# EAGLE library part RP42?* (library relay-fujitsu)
Power PCB Relay RP II/2 Schrack 2 pole 8 A Source: http://www.schrack.com/.. 5844.pdf

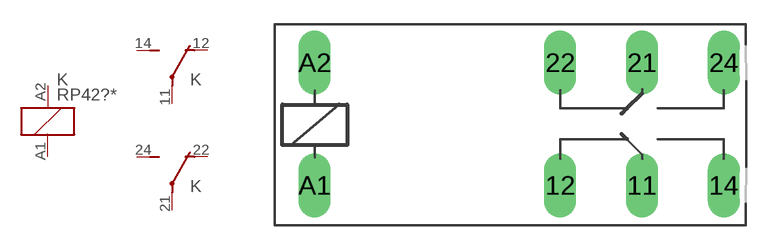
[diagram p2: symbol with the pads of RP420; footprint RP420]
Designator prefix K; gates 1=K 2=U 3=U

## RP420005, RP420006, RP420012, RP420024, RP420048, RP420060, RP420110  [RP420]
11  2:P  pas
12  2:O  pas
14  2:S  pas
21  3:P  pas
22  3:O  pas
24  3:S  pas
A1  1:2  pas
A2  1:1  pas

## RP421005, RP421006, RP421012, RP421024, RP421048, RP421060, RP421110  [RP420]
Pads as for RP420

## Footprint RP420 (pad centres in mm)
RELAY 2 x switch, Schrack
drill 1.321 long: 11 16.51,-3.81; 12 11.43,-3.81; 14 21.59,-3.81; 21 16.51,3.81; 22 11.43,3.81; 24 21.59,3.81; A1 -3.81,-3.81; A2 -3.81,3.81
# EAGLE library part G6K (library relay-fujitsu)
Low Signal Relay oeiwcsnts1.omron.com/.. D20G6K0100.pdf

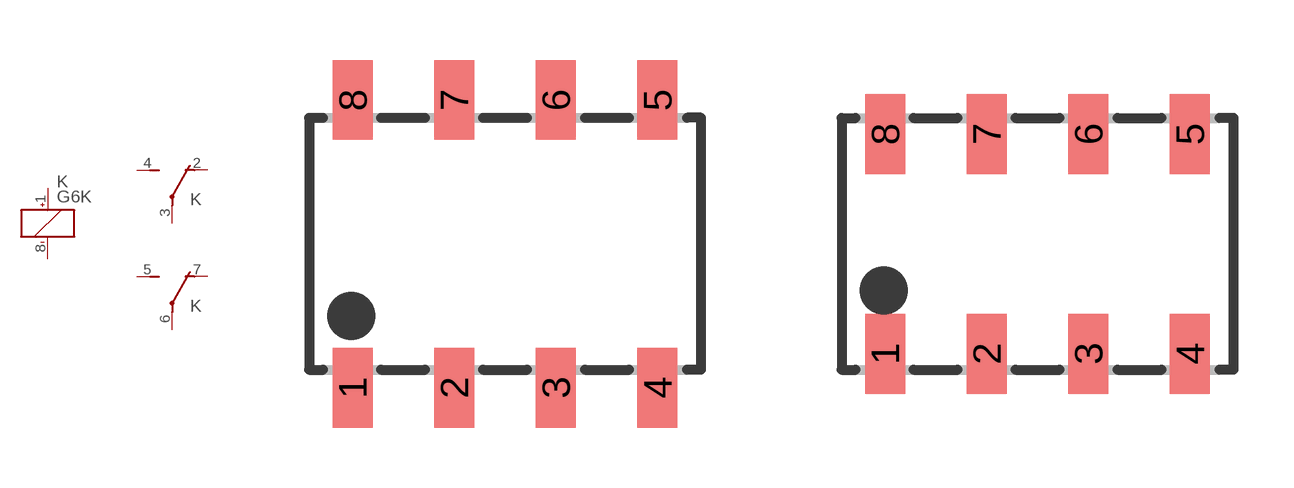
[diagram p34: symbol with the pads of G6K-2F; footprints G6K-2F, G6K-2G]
Designator prefix K; gates 1=K+- 2=U 3=U

## G6K-2F  [G6K-2F]
1  1:+  pas
2  2:O  pas
3  2:P  pas
4  2:S  pas
5  3:S  pas
6  3:P  pas
7  3:O  pas
8  1:-  pas

## G6K-2G  [G6K-2G]
Pads as for G6K-2F

## G6K-2P  [G6K-2P]
Pads as for G6K-2F

## G6K-2F-Y  [G6K-2F-Y]
Pads as for G6K-2F

## G6K-2G-Y  [G6K-2G-Y]
Pads as for G6K-2F

## G6K-2P-Y  [G6K-2P-Y]
Pads as for G6K-2F

## G6KU-2F-Y  [G6KU-2F-Y]
Pads as for G6K-2F

## G6KU-2G-Y  [G6KU-2G-Y]
Pads as for G6K-2F

## G6KU-2P-Y  [G6KU-2P-Y]
Pads as for G6K-2F

## Footprint G6K-2F (pad centres in mm)
Low Signal Relay oeiwcsnts1.omron.com/.. D20G6K0100.pdf
smd 1 x 2: 1 -3.81,-3.6; 2 -1.27,-3.6; 3 1.27,-3.6; 4 3.81,-3.6; 5 3.81,3.6; 6 1.27,3.6; 7 -1.27,3.6; 8 -3.81,3.6

## Footprint G6K-2G (pad centres in mm)
Low Signal Relay oeiwcsnts1.omron.com/.. D20G6K0100.pdf
smd 1 x 2: 1 -3.81,-2.75; 2 -1.27,-2.75; 3 1.27,-2.75; 4 3.81,-2.75; 5 3.81,2.75; 6 1.27,2.75; 7 -1.27,2.75; 8 -3.81,2.75

## Footprint G6K-2P (pad centres in mm)
Low Signal Relay oeiwcsnts1.omron.com/.. D20G6K0100.pdf
drill 0.8 octagon: 1 -2.54,-2.54; 2 0,-2.54; 3 2.54,-2.54; 4 5.08,-2.54; 5 5.08,2.54; 6 2.54,2.54; 7 0,2.54; 8 -2.54,2.54

## Footprint G6K-2F-Y (pad centres in mm)
Low Signal Relay oeiwcsnts1.omron.com/.. D20G6K0100.pdf
smd 1.2 x 1.8: 1 -3.8,-3.5; 2 -0.6,-3.5; 3 1.6,-3.5; 4 3.8,-3.5; 5 3.8,3.5; 6 1.6,3.5; 7 -0.6,3.5; 8 -3.8,3.5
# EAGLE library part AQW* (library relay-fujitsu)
PhotoMOS Relay NAiS Source: http://www.mew-europe.com/.. pti_en.pdf

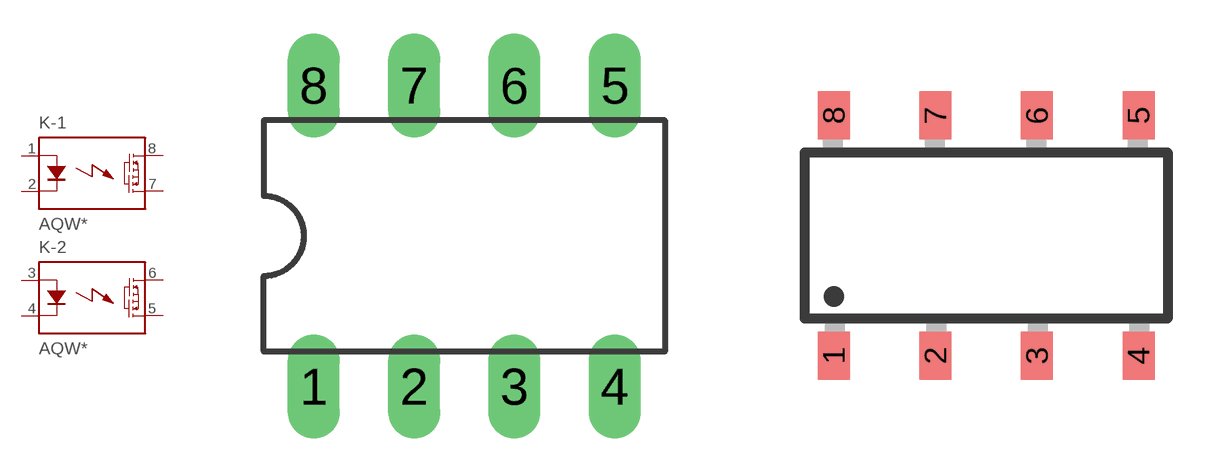
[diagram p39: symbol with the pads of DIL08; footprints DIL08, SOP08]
Designator prefix K; gates -1=PHOTO-RELAY-2S -2=PHOTO-RELAY-2S

## AQW21, AQW22, AQW25, AQW27, AQW41, AQW45, AQW654  [DIL08]
1  -1:A  pas
2  -1:K  pas
3  -2:A  pas
4  -2:K  pas
5  -2:D2  pas
6  -2:D1  pas
7  -1:D2  pas
8  -1:D1  pas

## AQW21SOP  [SOP08]
Pads as for DIL08

## AQW654SMD  [DIL08SMD]
Pads as for DIL08

## Footprint DIL08 (pad centres in mm)
Dual In Line Package
drill 0.813 long: 1 -3.81,-3.81; 2 -1.27,-3.81; 3 1.27,-3.81; 4 3.81,-3.81; 5 3.81,3.81; 6 1.27,3.81; 7 -1.27,3.81; 8 -3.81,3.81

## Footprint SOP08 (pad centres in mm)
SOP 08 - AQW21, AQW61 Series NAiS Source: http://www.mew-europe.com/.. pti_en.pdf
smd 0.8 x 1.2: 1 -3.81,-3; 2 -1.27,-3; 3 1.27,-3; 4 3.81,-3; 5 3.81,3; 6 1.27,3; 7 -1.27,3; 8 -3.81,3

## Footprint DIL08SMD (pad centres in mm)
DIL08 NAiS Source: http://www.mew-europe.com/.. pti_en.pdf
smd 1.5 x 1.9: 1 -3.81,-4.15; 2 -1.27,-4.15; 3 1.27,-4.15; 4 3.81,-4.15; 5 3.81,4.15; 6 1.27,4.15; 7 -1.27,4.15; 8 -3.81,4.15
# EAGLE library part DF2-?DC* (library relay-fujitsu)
HIGHLY SENSITIVE DIP MINIATURE RELAY NAiS Single side stable / 1 coil latching Source: http://www.mew-europe.com/.. en_ds_61002_0000.pdf

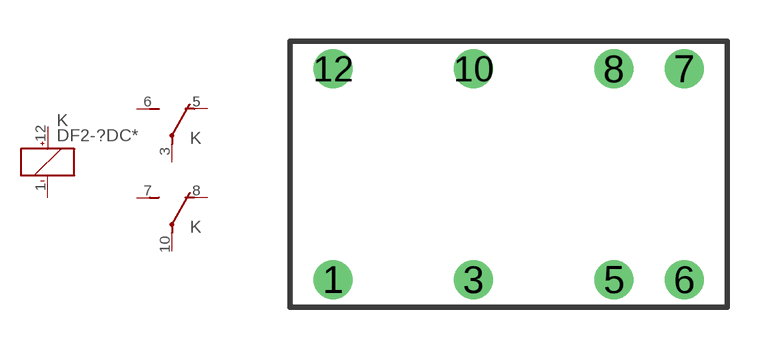
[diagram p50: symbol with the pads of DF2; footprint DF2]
Designator prefix K; gates 1=K+- 2=U 3=U

## DF2-DC1.5V, DF2-DC12V, DF2-DC24V, DF2-DC3V, DF2-DC5V, DF2-DC6V, DF2-DC9V  [DF2]
1  1:-  pas
3  2:P  pas
5  2:O  pas
6  2:S  pas
7  3:S  pas
8  3:O  pas
10  3:P  pas
12  1:+  pas

## DF2-L-DC1.5V, DF2-L-DC12V, DF2-L-DC24V, DF2-L-DC3V, DF2-L-DC5V, DF2-L-DC6V, DF2-L-DC9V  [DF2]
Pads as for DF2

## Footprint DF2 (pad centres in mm)
HIGHLY SENSITIVE DIP MINIATURE RELAY Source: http://www.mew-europe.com/.. en_ds_61002_0000.pdf
drill 0.9 round: 1 -6.35,-3.81; 3 -1.27,-3.81; 5 3.81,-3.81; 6 6.35,-3.81; 7 6.35,3.81; 8 3.81,3.81; 10 -1.27,3.81; 12 -6.35,3.81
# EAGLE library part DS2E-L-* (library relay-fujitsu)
DS-RELAYS HIGHLY SENSITIVE 1500 V FCC SURGE NAiS WITHSTANDING MINIATURE RELAY Source: http://www.mew-europe.com/.. en_ds_61005_0001.pdf

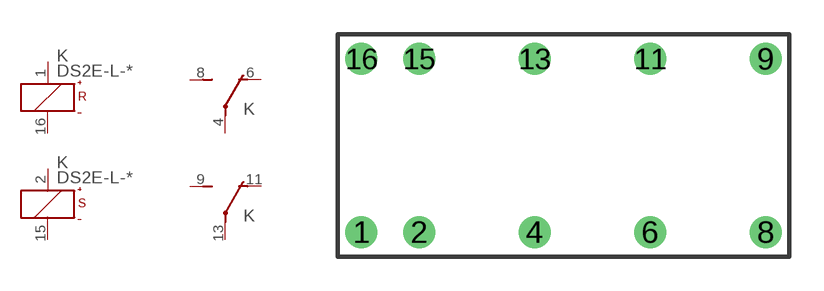
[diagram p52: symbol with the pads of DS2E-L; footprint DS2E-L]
Designator prefix K; gates 1=K+-R 2=K+-S 3=U 4=U

## DS2E-L-1.5V, DS2E-L-12V, DS2E-L-24V, DS2E-L-3V, DS2E-L-48V, DS2E-L-5V, DS2E-L-6V, DS2E-L-9V  [DS2E-L]
1  1:+  pas
2  2:+  pas
4  3:P  pas
6  3:O  pas
8  3:S  pas
9  4:S  pas
11  4:O  pas
13  4:P  pas
15  2:-  pas
16  1:-  pas

## Footprint DS2E-L (pad centres in mm)
DS-RELAYS HIGHLY SENSITIVE 1500 V FCC SURGE NAiS WITHSTANDING MINIATURE RELAY Source: http://www.mew-europe.com/.. en_ds_61005_0001.pdf
drill 0.9 round: 1 -8.89,-3.81; 2 -6.35,-3.81; 4 -1.27,-3.81; 6 3.81,-3.81; 8 8.89,-3.81; 9 8.89,3.81; 11 3.81,3.81; 13 -1.27,3.81; 15 -6.35,3.81; 16 -8.89,3.81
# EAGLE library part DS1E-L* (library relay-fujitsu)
DS-RELAYS HIGHLY SENSITIVE 1500 V FCC SURGE NAiS WITHSTANDING MINIATURE RELAY Source: http://www.mew-europe.com/.. en_ds_61005_0001.pdf

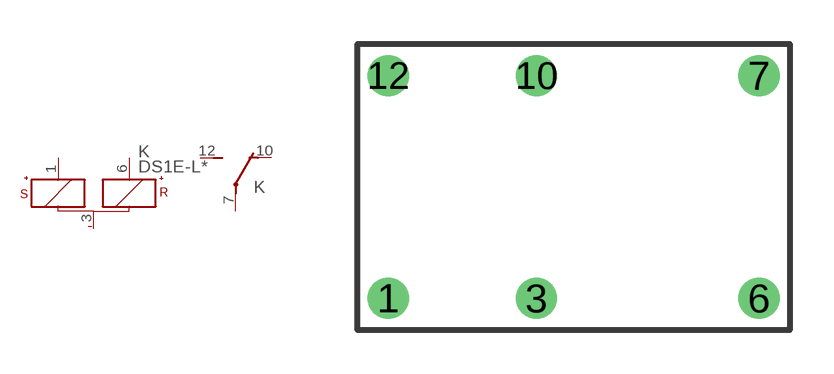
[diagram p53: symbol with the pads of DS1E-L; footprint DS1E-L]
Designator prefix K; gates 2=U 1=+KS+KR-

## DS1E-L1.5V, DS1E-L12V, DS1E-L24V, DS1E-L3V, DS1E-L48V, DS1E-L5V, DS1E-L6V, DS1E-L9V  [DS1E-L]
1  1:S+  pas
3  1:-  pas
6  1:R+  pas
7  2:P  pas
10  2:O  pas
12  2:S  pas

## Footprint DS1E-L (pad centres in mm)
DS-RELAYS HIGHLY SENSITIVE 1500 V FCC SURGE NAiS WITHSTANDING MINIATURE RELAY Source: http://www.mew-europe.com/.. en_ds_61005_0001.pdf
drill 0.9 round: 1 -6.35,-3.81; 3 -1.27,-3.81; 6 6.35,-3.81; 7 6.35,3.81; 10 -1.27,3.81; 12 -6.35,3.81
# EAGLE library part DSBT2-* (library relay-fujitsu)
DS-BT RELAYS 4,000 V BREAKDOWN VOLTAGE NAiS Source: http://www.mew-europe.com/.. en_ds_61005_0010.pdf

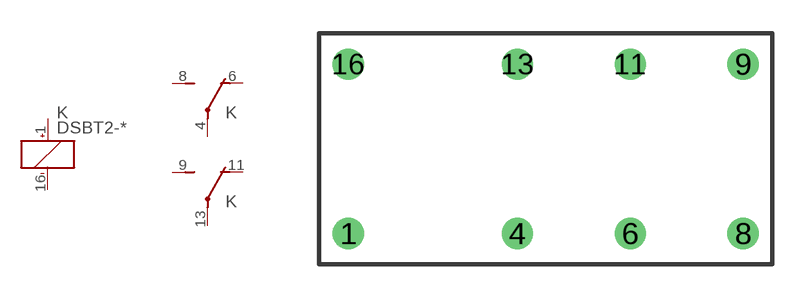
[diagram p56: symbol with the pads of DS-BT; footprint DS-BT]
Designator prefix K; gates 1=K+- 2=U 3=U

## DSBT2-M-2D-DC1.5V, DSBT2-M-2D-DC12V, DSBT2-M-2D-DC24V, DSBT2-M-2D-DC3V, DSBT2-M-2D-DC5V, DSBT2-M-2D-DC6V, DSBT2-M-2D-DC9V, DSBT2-S-DC1.5V, DSBT2-S-DC12V, DSBT2-S-DC24V, DSBT2-S-DC3V, DSBT2-S-DC5V, DSBT2-S-DC6V, DSBT2-S-DC9V  [DS-BT]
1  1:+  pas
4  2:P  pas
6  2:O  pas
8  2:S  pas
9  3:S  pas
11  3:O  pas
13  3:P  pas
16  1:-  pas

## Footprint DS-BT (pad centres in mm)
DS-BT RELAYS 4,000 V BREAKDOWN VOLTAGE NAiS Source: http://www.mew-europe.com/.. en_ds_61005_0010.pdf
drill 0.9 round: 1 -8.89,-3.81; 4 -1.27,-3.81; 6 3.81,-3.81; 8 8.89,-3.81; 9 8.89,3.81; 11 3.81,3.81; 13 -1.27,3.81; 16 -8.89,3.81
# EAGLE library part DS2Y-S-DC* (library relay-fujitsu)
MINIATURE RELAY NAiS Source: http://www.mew-europe.com/.. en_ds_61005_0023.pdf

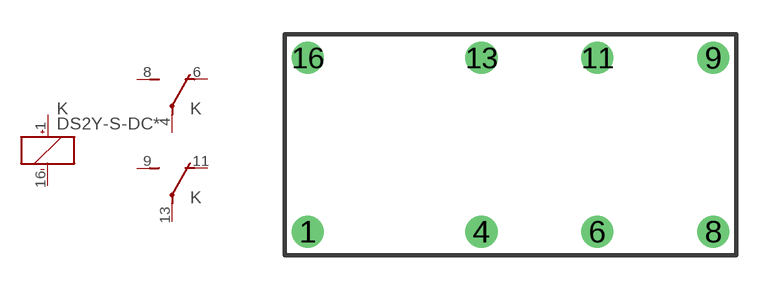
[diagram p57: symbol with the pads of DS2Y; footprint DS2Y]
Designator prefix K; gates 1=K+- 2=U 3=U

## DS2Y-S-DC1.5V, DS2Y-S-DC12V, DS2Y-S-DC24V, DS2Y-S-DC3V, DS2Y-S-DC48V, DS2Y-S-DC5V, DS2Y-S-DC6V, DS2Y-S-DC9V  [DS2Y]
1  1:+  pas
4  2:P  pas
6  2:O  pas
8  2:S  pas
9  3:S  pas
11  3:O  pas
13  3:P  pas
16  1:-  pas

## Footprint DS2Y (pad centres in mm)
MINIATURE RELAY NAiS Source: http://www.mew-europe.com/.. en_ds_61005_0023.pdf
drill 0.9 round: 1 -8.89,-3.81; 4 -1.27,-3.81; 6 3.81,-3.81; 8 8.89,-3.81; 9 8.89,3.81; 11 3.81,3.81; 13 -1.27,3.81; 16 -8.89,3.81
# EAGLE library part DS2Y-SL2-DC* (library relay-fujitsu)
MINIATURE RELAY NAiS Source: http://www.mew-europe.com/.. en_ds_61005_0023.pdf

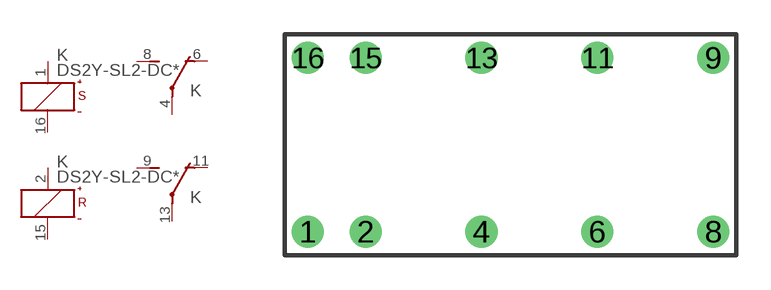
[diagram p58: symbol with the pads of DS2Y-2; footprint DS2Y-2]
Designator prefix K; gates 1=U 2=U S=K+-S R=K+-R

## DS2Y-SL2-DC1.5V, DS2Y-SL2-DC12V, DS2Y-SL2-DC24V, DS2Y-SL2-DC3V, DS2Y-SL2-DC48V, DS2Y-SL2-DC5V, DS2Y-SL2-DC6V, DS2Y-SL2-DC9V  [DS2Y-2]
1  S:+  pas
2  R:+  pas
4  1:P  pas
6  1:O  pas
8  1:S  pas
9  2:S  pas
11  2:O  pas
13  2:P  pas
15  R:-  pas
16  S:-  pas

## Footprint DS2Y-2 (pad centres in mm)
MINIATURE RELAY NAiS Source: http://www.mew-europe.com/.. en_ds_61005_0023.pdf
drill 0.9 round: 1 -8.89,-3.81; 2 -6.35,-3.81; 4 -1.27,-3.81; 6 3.81,-3.81; 8 8.89,-3.81; 9 8.89,3.81; 11 3.81,3.81; 13 -1.27,3.81; 15 -6.35,3.81; 16 -8.89,3.81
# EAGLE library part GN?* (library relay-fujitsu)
ULTRA-SMALL PACKAGE SLIM POLARIZED RELAY NAiS Source: http://www.mew-europe.com/.. en_ds_61007_0000.pdf

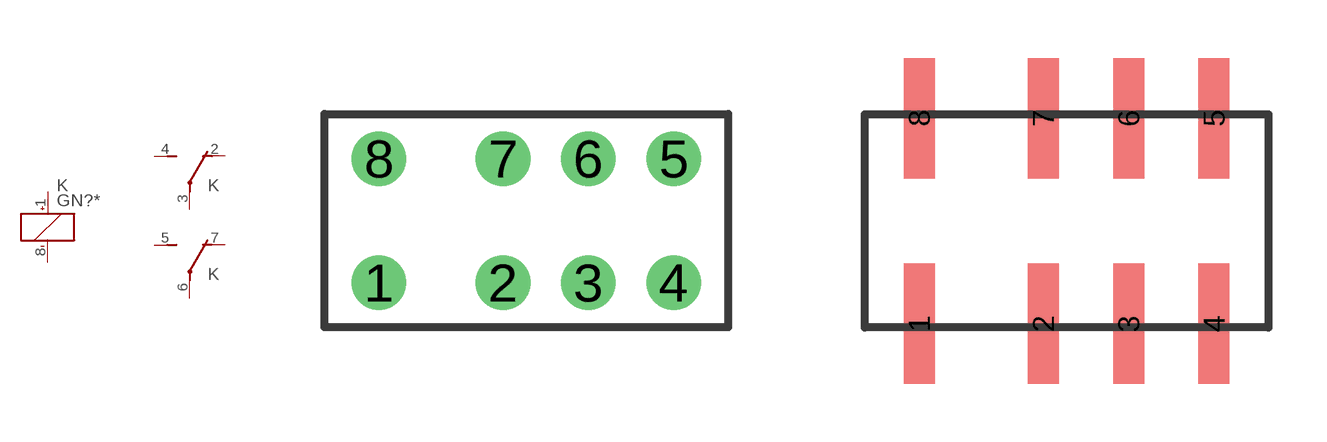
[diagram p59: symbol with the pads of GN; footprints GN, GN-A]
Designator prefix K; gates R=K+- S=U T=U

## GN20003, GN20006, GN20009, GN20012, GN2001H, GN20024, GN2004H  [GN]
1  R:+  pas
2  S:O  pas
3  S:P  pas
4  S:S  pas
5  T:S  pas
6  T:P  pas
7  T:O  pas
8  R:-  pas

## GN21003, GN21006, GN21009, GN21012, GN2101H, GN21024, GN2104H  [GN]
1  R:-  pas
2  S:O  pas
3  S:P  pas
4  S:S  pas
5  T:S  pas
6  T:P  pas
7  T:O  pas
8  R:+  pas

## GN200A03, GN200A06, GN200A09, GN200A12, GN200A1H, GN200A24, GN200A4H  [GN-A]
Pads as for GN

## GN200S03, GN200S06, GN200S09, GN200S12, GN200S1H, GN200S24, GN200S4H  [GN-S]
Pads as for GN

## GN210A03, GN210A06, GN210A09, GN210A12, GN210A1H, GN210A24, GN210A4H  [GN-A]
Pads as for GN

## GN210S03, GN210S06, GN210S09, GN210S12, GN210S1H, GN210S24, GN210S4H  [GN-S]
Pads as for GN

## Footprint GN (pad centres in mm)
ULTRA-SMALL PACKAGE SLIM POLARIZED RELAY NAiS Source: http://www.mew-europe.com/.. en_ds_61007_0000.pdf
drill 0.9 round: 1 -3.835,-1.6; 2 -0.635,-1.6; 3 1.565,-1.6; 4 3.765,-1.6; 5 3.765,1.6; 6 1.565,1.6; 7 -0.635,1.6; 8 -3.835,1.6

## Footprint GN-A (pad centres in mm)
ULTRA-SMALL PACKAGE SLIM POLARIZED RELAY NAiS Source: http://www.mew-europe.com/.. en_ds_61007_0000.pdf
smd 0.8 x 3.1: 1 -3.835,-2.65; 2 -0.635,-2.65; 3 1.565,-2.65; 4 3.765,-2.65; 5 3.765,2.65; 6 1.565,2.65; 7 -0.635,2.65; 8 -3.835,2.65

## Footprint GN-S (pad centres in mm)
ULTRA-SMALL PACKAGE SLIM POLARIZED RELAY NAiS Source: http://www.mew-europe.com/.. en_ds_61007_0000.pdf
smd 0.8 x 2.25: 1 -3.835,-2.225; 2 -0.635,-2.225; 3 1.565,-2.225; 4 3.765,-2.225; 5 3.765,2.225; 6 1.565,2.225; 7 -0.635,2.225; 8 -3.835,2.225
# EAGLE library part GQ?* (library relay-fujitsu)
ULTRA-SMALL PACKAGE FLAT POLARIZED RELAY NAiS Source: http://www.mew-europe.com/.. en_ds_61008_0000.pdf

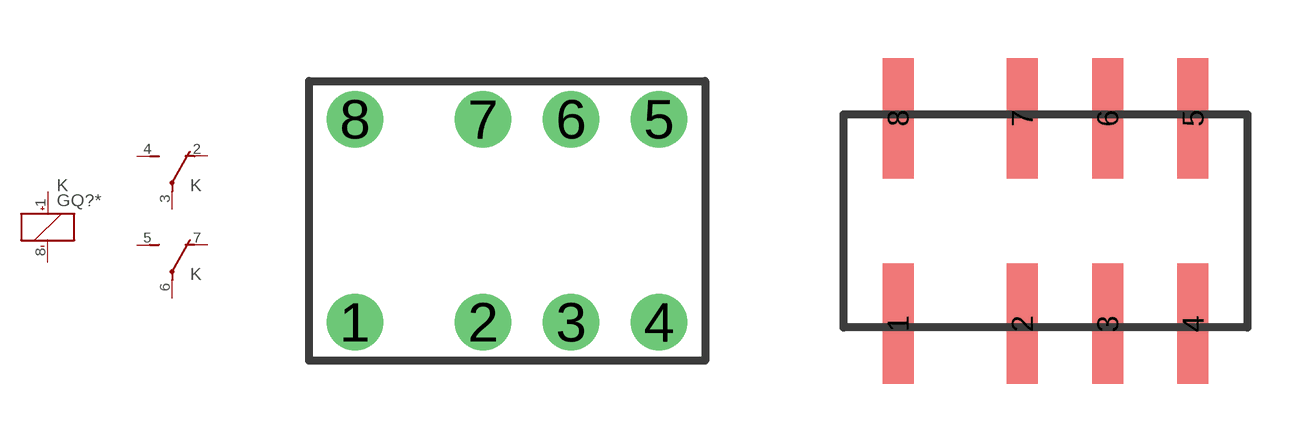
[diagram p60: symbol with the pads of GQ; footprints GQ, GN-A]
Designator prefix K; gates 1=K+- 2=U 3=U

## GQ20003, GQ20006, GQ20009, GQ20012, GQ2001H, GQ20024, GQ2004H  [GQ]
1  1:+  pas
2  2:O  pas
3  2:P  pas
4  2:S  pas
5  3:S  pas
6  3:P  pas
7  3:O  pas
8  1:-  pas

## GQ200A03, GQ200A06, GQ200A09, GQ200A12, GQ200A1H, GQ200A24, GQ200A4H  [GN-A]
Pads as for GQ

## GQ200S03, GQ200S06, GQ200S09, GQ200S12, GQ200S1H, GQ200S24, GQ200S4H  [GN-S]
Pads as for GQ

## GQ21003, GQ21006, GQ21009, GQ21012, GQ2101H, GQ21024, GQ2104H  [GQ]
1  1:-  pas
2  2:O  pas
3  2:P  pas
4  2:S  pas
5  3:S  pas
6  3:P  pas
7  3:O  pas
8  1:+  pas

## GQ210A03, GQ210A06, GQ210A09, GQ210A12, GQ210A1H, GQ210A24, GQ210A4H  [GQ-A]
Pads as for GQ

## GQ210S03, GQ210S06, GQ210S09, GQ210S12V, GQ210S1H, GQ210S24, GQ210S4H  [GN-S]
Pads as for GQ

## Footprint GQ (pad centres in mm)
ULTRA-SMALL PACKAGE FLAT POLARIZED RELAY NAiS Source: http://www.mew-europe.com/.. en_ds_61008_0000.pdf
drill 0.9 round: 1 -3.8,-2.54; 2 -0.6,-2.54; 3 1.6,-2.54; 4 3.8,-2.54; 5 3.8,2.54; 6 1.6,2.54; 7 -0.6,2.54; 8 -3.8,2.54

## Footprint GN-A (pad centres in mm)
ULTRA-SMALL PACKAGE SLIM POLARIZED RELAY NAiS Source: http://www.mew-europe.com/.. en_ds_61007_0000.pdf
smd 0.8 x 3.1: 1 -3.835,-2.65; 2 -0.635,-2.65; 3 1.565,-2.65; 4 3.765,-2.65; 5 3.765,2.65; 6 1.565,2.65; 7 -0.635,2.65; 8 -3.835,2.65

## Footprint GN-S (pad centres in mm)
ULTRA-SMALL PACKAGE SLIM POLARIZED RELAY NAiS Source: http://www.mew-europe.com/.. en_ds_61007_0000.pdf
smd 0.8 x 2.25: 1 -3.835,-2.225; 2 -0.635,-2.225; 3 1.565,-2.225; 4 3.765,-2.225; 5 3.765,2.225; 6 1.565,2.225; 7 -0.635,2.225; 8 -3.835,2.225

## Footprint GQ-A (pad centres in mm)
ULTRA-SMALL PACKAGE FLAT POLARIZED RELAY NAiS Source: http://www.mew-europe.com/.. en_ds_61008_0000.pdf
smd 0.8 x 2.66: 1 -3.8,-3.37; 2 -0.6,-3.37; 3 1.6,-3.37; 4 3.8,-3.37; 5 3.8,3.37; 6 1.6,3.37; 7 -0.6,3.37; 8 -3.8,3.37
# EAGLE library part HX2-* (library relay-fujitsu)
Compact & Slim 2 Form C Non-polarized Relay NAiS Source: http://www.mew-europe.com/.. en_ds_61011_0000.pdf

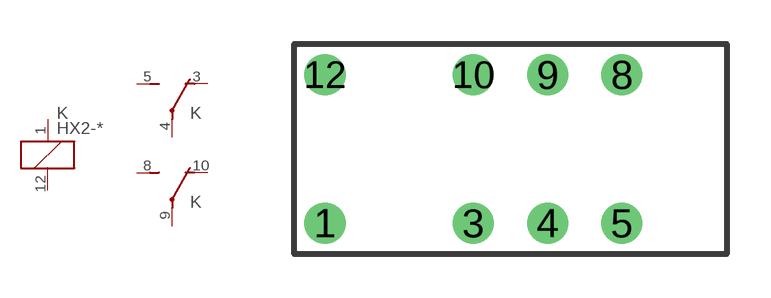
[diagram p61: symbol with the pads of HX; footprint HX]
Designator prefix K; gates 1=K 2=U 3=U

## HX2-1.5V, HX2-12V, HX2-24V, HX2-3V, HX2-4.5V, HX2-5V, HX2-6V, HX2-9V  [HX]
1  1:1  pas
3  2:O  pas
4  2:P  pas
5  2:S  pas
8  3:S  pas
9  3:P  pas
10  3:O  pas
12  1:2  pas

## Footprint HX (pad centres in mm)
Compact & Slim 2 Form C Non-polarized Relay NAiS Source: http://www.mew-europe.com/.. en_ds_61011_0000.pdf
drill 0.9 round: 1 -6.35,-2.54; 3 -1.27,-2.54; 4 1.27,-2.54; 5 3.81,-2.54; 8 3.81,2.54; 9 1.27,2.54; 10 -1.27,2.54; 12 -6.35,2.54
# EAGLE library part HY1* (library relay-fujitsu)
Non-polarized 1 Form C Relay NAiS Source: http://www.mew-europe.com/.. en_ds_61012_0000.pdf

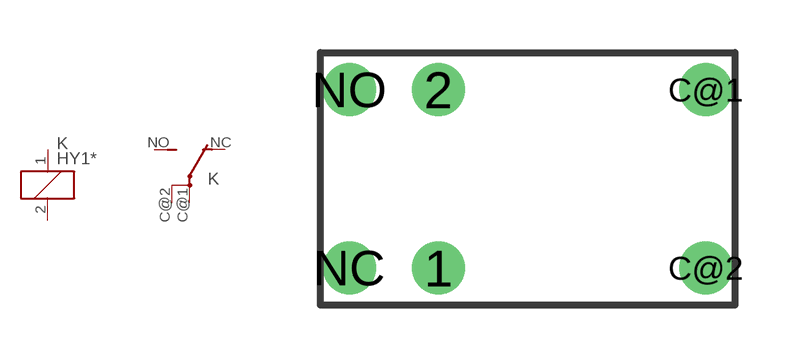
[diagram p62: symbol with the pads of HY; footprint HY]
Designator prefix K; gates 1=K 2=U1

## HY1-1.5V, HY1-12V, HY1-24V, HY1-3V, HY1-4.5V, HY1-5V, HY1-6V, HY1-9V, HY1Z-1.5V, HY1Z-12V, HY1Z-24V, HY1Z-3V, HY1Z-4.5V, HY1Z-5V, HY1Z-6V, HY1Z-9V  [HY]
1  1:1  pas
2  1:2  pas
C@1  2:P  pas
C@2  2:P  pas
NC  2:O  pas
NO  2:S  pas

## Footprint HY (pad centres in mm)
Non-polarized 1 Form C Relay NAiS Source: http://www.mew-europe.com/.. en_ds_61012_0000.pdf
drill 1 round: 1 -2.54,-2.54; 2 -2.54,2.54; C@1 5.08,2.54; C@2 5.08,-2.54; NC -5.08,-2.54; NO -5.08,2.54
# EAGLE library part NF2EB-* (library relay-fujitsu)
FLATPACK RELAY NAiS Source: http://www.mew-europe.com/.. en_ds_61014_0000.pdf

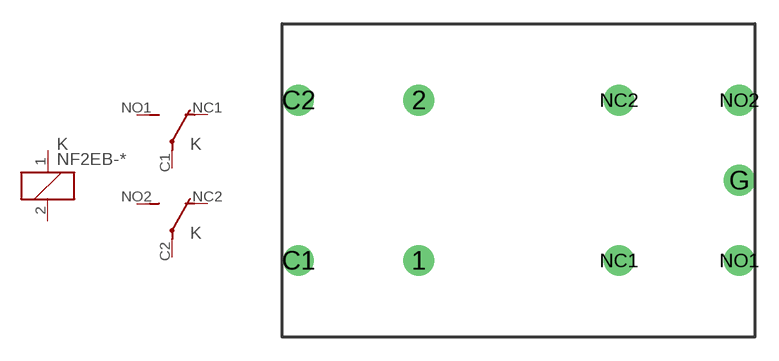
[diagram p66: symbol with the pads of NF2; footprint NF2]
Designator prefix K; gates _=K G$1=U G$2=U

## NF2EB-12V, NF2EB-24V, NF2EB-48V, NF2EB-5V, NF2EB-6V  [NF2]
1  _:1  pas
2  _:2  pas
C1  G$1:P  pas
C2  G$2:P  pas
NC1  G$1:O  pas
NC2  G$2:O  pas
NO1  G$1:S  pas
NO2  G$2:S  pas

## Footprint NF2 (pad centres in mm)
FLATPACK RELAY NAiS Source: http://www.mew-europe.com/.. en_ds_61014_0000.pdf
drill 1.3 round: 1 -6.35,-5.08; 2 -6.35,5.08; C1 -13.97,-5.08; C2 -13.97,5.08; G 13.97,0; NC1 6.35,-5.08; NC2 6.35,5.08; NO1 13.97,-5.08; NO2 13.97,5.08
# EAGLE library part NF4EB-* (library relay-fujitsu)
FLATPACK RELAY NAiS Source: http://www.mew-europe.com/.. en_ds_61014_0000.pdf

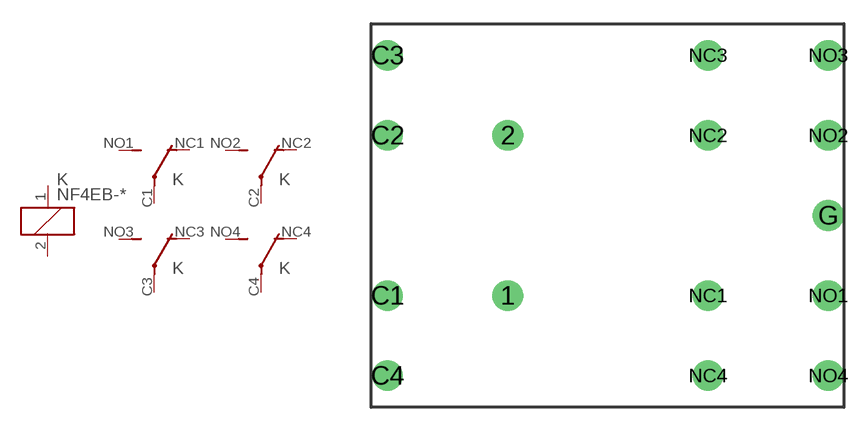
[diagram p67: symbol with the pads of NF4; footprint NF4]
Designator prefix K; gates _=K 1=U 2=U 3=U 4=U

## NF4EB-12V, NF4EB-24V, NF4EB-48V, NF4EB-5V, NF4EB-6V  [NF4]
1  _:1  pas
2  _:2  pas
C1  1:P  pas
C2  2:P  pas
C3  3:P  pas
C4  4:P  pas
NC1  1:O  pas
NC2  2:O  pas
NC3  3:O  pas
NC4  4:O  pas
NO1  1:S  pas
NO2  2:S  pas
NO3  3:S  pas
NO4  4:S  pas

## Footprint NF4 (pad centres in mm)
FLATPACK RELAY NAiS Source: http://www.mew-europe.com/.. en_ds_61014_0000.pdf
drill 1.3 round: 1 -6.35,-5.08; 2 -6.35,5.08; C1 -13.97,-5.08; C2 -13.97,5.08; C3 -13.97,10.16; C4 -13.97,-10.16; G 13.97,0; NC1 6.35,-5.08; NC2 6.35,5.08; NC3 6.35,10.16; NC4 6.35,-10.16; NO1 13.97,-5.08; NO2 13.97,5.08; NO3 13.97,10.16; NO4 13.97,-10.16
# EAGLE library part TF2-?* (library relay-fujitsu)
SMALL POLARIZED RELAY WITH HIGH SENSITIVITY NAiS Source: http://www.mew-europe.com/.. en_ds_61017_0000.pdf

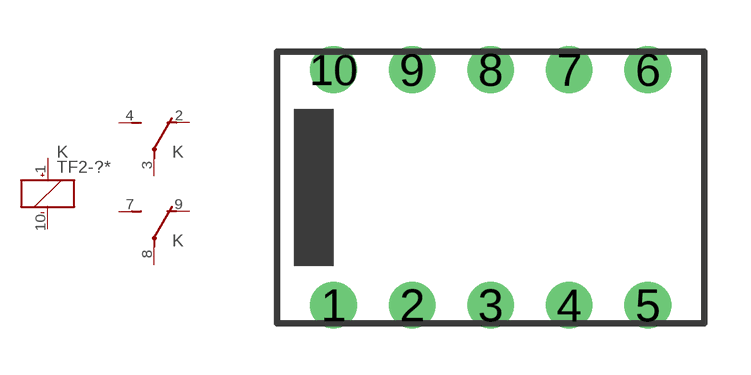
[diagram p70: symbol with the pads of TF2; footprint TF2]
Designator prefix K; gates -=K+- 1=U 2=U

## TF2--12V, TF2--24V, TF2--3V, TF2--4.5V, TF2--48V, TF2--5V, TF2--6V, TF2--9V  [TF2]
1  -:+  pas
2  1:O  pas
3  1:P  pas
4  1:S  pas
7  2:S  pas
8  2:P  pas
9  2:O  pas
10  -:-  pas

## TF2-L-12V, TF2-L-24V, TF2-L-3V, TF2-L-4.5V, TF2-L-5V, TF2-L-6V, TF2-L-9V  [TF2]
1  -:-  pas
2  1:O  pas
3  1:P  pas
4  1:S  pas
7  2:S  pas
8  2:P  pas
9  2:O  pas
10  -:+  pas

## Footprint TF2 (pad centres in mm)
SMALL POLARIZED RELAY WITH HIGH SENSITIVITY NAiS Source: http://www.mew-europe.com/.. en_ds_61017_0000.pdf
drill 1 round: 1 -5.08,-3.81; 2 -2.54,-3.81; 3 0,-3.81; 4 2.54,-3.81; 5 5.08,-3.81; 6 5.08,3.81; 7 2.54,3.81; 8 0,3.81; 9 -2.54,3.81; 10 -5.08,3.81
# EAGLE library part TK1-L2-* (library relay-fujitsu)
ULTRA LOW PROFILE 2 AMP. POLARIZED RELAY NAiS 2 coil latching Source: http://www.mew-europe.com/.. en_ds_61018_0000.pdf

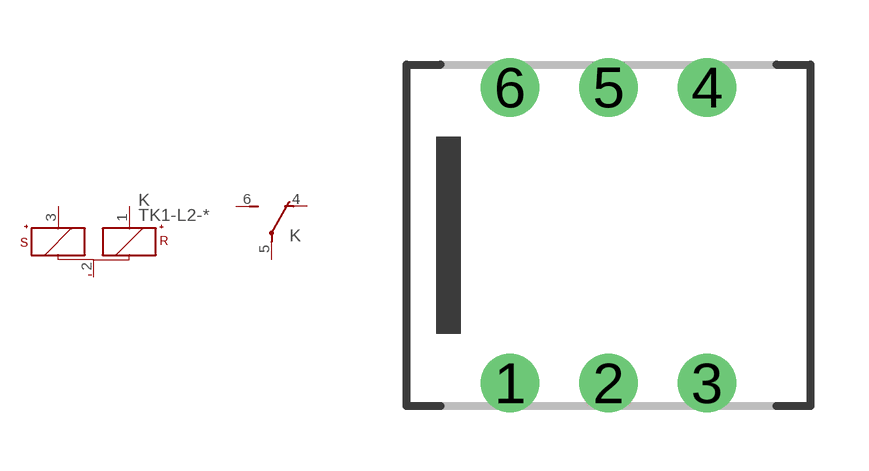
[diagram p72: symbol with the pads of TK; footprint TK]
Designator prefix K; gates -=+KS+KR- G$1=U

## TK1-L2-1.5V, TK1-L2-12V, TK1-L2-24V, TK1-L2-3V, TK1-L2-4.5V, TK1-L2-5V, TK1-L2-6V, TK1-L2-9V, TK1-L2-H-1.5V, TK1-L2-H-12V, TK1-L2-H-24V, TK1-L2-H-3V, TK1-L2-H-5V, TK1-L2-H-6V, TK1-L2-H-9V  [TK]
1  -:R+  pas
2  -:-  pas
3  -:S+  pas
4  G$1:O  pas
5  G$1:P  pas
6  G$1:S  pas

## Footprint TK (pad centres in mm)
ULTRA LOW PROFILE 2 AMP. POLARIZED RELAY NAiS Source: http://www.mew-europe.com/.. en_ds_61018_0000.pdf
drill 1 round: 1 -2.54,-3.81; 2 0,-3.81; 3 2.54,-3.81; 4 2.54,3.81; 5 0,3.81; 6 -2.54,3.81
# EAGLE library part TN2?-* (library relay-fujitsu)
SLIM POLARIZED RELAY NAiS Source: http://www.mew-europe.com/.. en_ds_61019_0000.pdf

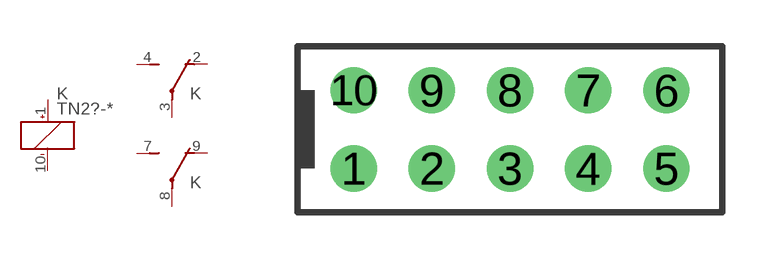
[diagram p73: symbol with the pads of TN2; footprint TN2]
Designator prefix K; gates -=K+- 1=U 2=U

## TN2-12V, TN2-24V, TN2-3V, TN2-4.5V, TN2-48V, TN2-5V, TN2-6V, TN2-9V  [TN2]
1  -:+  pas
2  1:O  pas
3  1:P  pas
4  1:S  pas
7  2:S  pas
8  2:P  pas
9  2:O  pas
10  -:-  pas

## TN2-L-12V, TN2-L-24V, TN2-L-3V, TN2-L-4.5V, TN2-L-5., TN2-L-6V, TN2-L-9V  [TN2]
1  -:-  pas
2  1:O  pas
3  1:P  pas
4  1:S  pas
7  2:S  pas
8  2:P  pas
9  2:O  pas
10  -:+  pas

## Footprint TN2 (pad centres in mm)
SLIM POLARIZED RELAY NAiS Source: http://www.mew-europe.com/.. en_ds_61019_0000.pdf
drill 1 round: 1 -5.08,-1.27; 2 -2.54,-1.27; 3 0,-1.27; 4 2.54,-1.27; 5 5.08,-1.27; 6 5.08,1.27; 7 2.54,1.27; 8 0,1.27; 9 -2.54,1.27; 10 -5.08,1.27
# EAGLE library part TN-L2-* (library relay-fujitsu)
SLIM POLARIZED RELAY NAiS 2 coil latched Source: http://www.mew-europe.com/.. en_ds_61019_0000.pdf

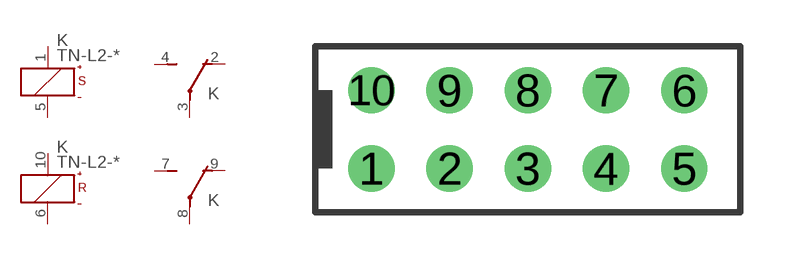
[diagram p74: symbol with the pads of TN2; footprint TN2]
Designator prefix K; gates S=K+-S R=K+-R 1=U 2=U

## TN-L2-12V, TN-L2-24V, TN-L2-3V, TN-L2-4.5V, TN-L2-5V, TN-L2-6V, TN-L2-9V  [TN2]
1  S:+  pas
2  1:O  pas
3  1:P  pas
4  1:S  pas
5  S:-  pas
6  R:-  pas
7  2:S  pas
8  2:P  pas
9  2:O  pas
10  R:+  pas

## Footprint TN2 (pad centres in mm)
SLIM POLARIZED RELAY NAiS Source: http://www.mew-europe.com/.. en_ds_61019_0000.pdf
drill 1 round: 1 -5.08,-1.27; 2 -2.54,-1.27; 3 0,-1.27; 4 2.54,-1.27; 5 5.08,-1.27; 6 5.08,1.27; 7 2.54,1.27; 8 0,1.27; 9 -2.54,1.27; 10 -5.08,1.27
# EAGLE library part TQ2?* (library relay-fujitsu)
LOW PROFILE 2 FORM C RELAY NAiS Source: http://www.mew-europe.com/.. en_ds_61020_0001.pdf Source: http://www.mew-europe.com/.. en_ds_61020_0004.pdf

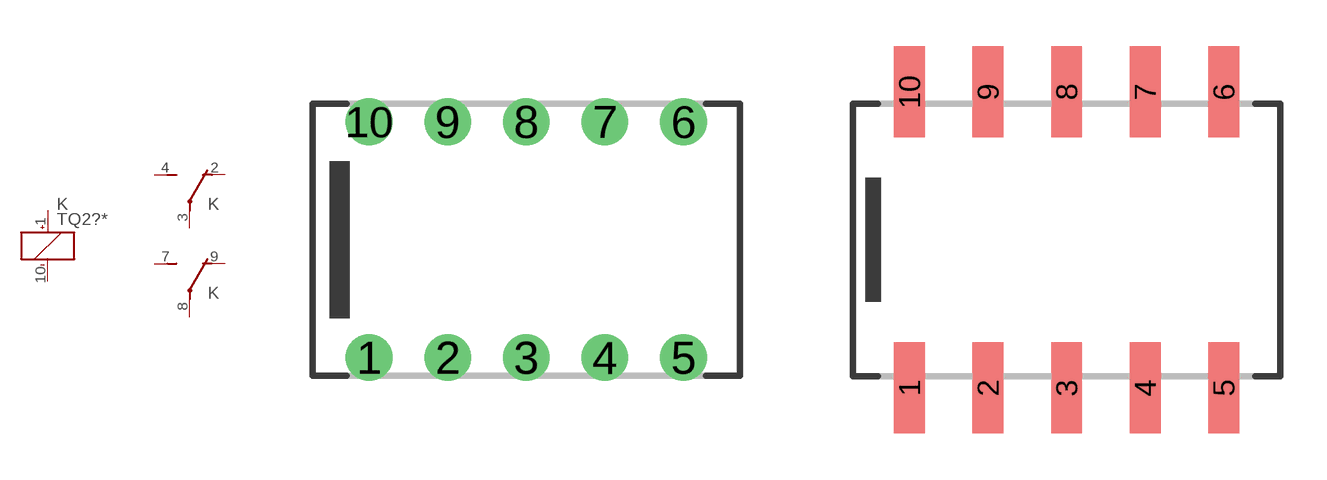
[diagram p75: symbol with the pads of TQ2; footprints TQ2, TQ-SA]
Designator prefix K; gates _=K+- 1=U 2=U

## TQ2-12V, TQ2-24V, TQ2-3V, TQ2-4.5V, TQ2-48V, TQ2-5V, TQ2-6V, TQ2-9V  [TQ2]
1  _:+  pas
2  1:O  pas
3  1:P  pas
4  1:S  pas
7  2:S  pas
8  2:P  pas
9  2:O  pas
10  _:-  pas

## TQ2-L-12V, TQ2-L-24V, TQ2-L-3V, TQ2-L-4.5V, TQ2-L-5V, TQ2-L-6V, TQ2-L-9V  [TQ2]
1  _:-  pas
2  1:O  pas
3  1:P  pas
4  1:S  pas
7  2:S  pas
8  2:P  pas
9  2:O  pas
10  _:+  pas

## TQ2-SA-1.5V, TQ2-SA-12V, TQ2-SA-24V, TQ2-SA-3V, TQ2-SA-4.5V, TQ2-SA-48V, TQ2-SA-5V, TQ2-SA-6V, TQ2-SA-9V  [TQ-SA]
Pads as for TQ2

## TQ2SA-L-1.5V, TQ2SA-L-12V, TQ2SA-L-24V, TQ2SA-L-3V, TQ2SA-L-4.5V, TQ2SA-L-5V, TQ2SA-L-6V, TQ2SA-L-9V  [TQ-SA]
Pads as for TQ2

## TQ2-SL-1.5V, TQ2-SL-12V, TQ2-SL-24V, TQ2-SL-3V, TQ2-SL-4.5V, TQ2-SL-5V, TQ2-SL-6V, TQ2-SL-9V  [TQ-SL]
Pads as for TQ2

## TQ2SL-L-1.5V, TQ2SL-L-12V, TQ2SL-L-24V, TQ2SL-L-3V, TQ2SL-L-4.5V, TQ2SL-L-5V, TQ2SL-L-6V, TQ2SL-L-9V  [TQ-SL]
Pads as for TQ2

## TQ2-SS-1.5V, TQ2-SS-12V, TQ2-SS-24V, TQ2-SS-3V, TQ2-SS-4.5V, TQ2-SS-48V, TQ2-SS-5V, TQ2-SS-6V, TQ2-SS-9V  [TQ-SS]
Pads as for TQ2

## TQ2SS-L-1.5V, TQ2SS-L-12V, TQ2SS-L-24V, TQ2SS-L-3V, TQ2SS-L-4.5V, TQ2SS-L-5V, TQ2SS-L-6V, TQ2SS-L-9V  [TQ-SS]
Pads as for TQ2

## Footprint TQ2 (pad centres in mm)
LOW PROFILE 2 FORM C RELAY NAiS Source: http://www.mew-europe.com/.. en_ds_61020_0001.pdf
drill 1 round: 1 -5.08,-3.81; 2 -2.54,-3.81; 3 0,-3.81; 4 2.54,-3.81; 5 5.08,-3.81; 6 5.08,3.81; 7 2.54,3.81; 8 0,3.81; 9 -2.54,3.81; 10 -5.08,3.81

## Footprint TQ-SA (pad centres in mm)
LOW-PROFILE TQ-SMD RELAYS NAiS Source: http://www.mew-europe.com/.. en_ds_61021_0004.pdf
smd 1 x 2.94: 1 -5.08,-4.78; 2 -2.54,-4.78; 3 0,-4.78; 4 2.54,-4.78; 5 5.08,-4.78; 6 5.08,4.78; 7 2.54,4.78; 8 0,4.78; 9 -2.54,4.78; 10 -5.08,4.78

## Footprint TQ-SL (pad centres in mm)
LOW-PROFILE TQ-SMD RELAYS NAiS Source: http://www.mew-europe.com/.. en_ds_61021_0004.pdf
smd 1 x 2.94: 1 -5.08,-4.78; 2 -2.54,-4.78; 3 0,-4.78; 4 2.54,-4.78; 5 5.08,-4.78; 6 5.08,4.78; 7 2.54,4.78; 8 0,4.78; 9 -2.54,4.78; 10 -5.08,4.78

## Footprint TQ-SS (pad centres in mm)
LOW-PROFILE TQ-SMD RELAYS NAiS Source: http://www.mew-europe.com/.. en_ds_61021_0004.pdf
smd 1 x 1.84: 1 -5.08,-4.23; 2 -2.54,-4.23; 3 0,-4.23; 4 2.54,-4.23; 5 5.08,-4.23; 6 5.08,4.23; 7 2.54,4.23; 8 0,4.23; 9 -2.54,4.23; 10 -5.08,4.23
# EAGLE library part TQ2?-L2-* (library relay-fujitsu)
LOW PROFILE 2 FORM C RELAY NAiS 2 coil latching Source: http://www.mew-europe.com/.. en_ds_61020_0001.pdf Source: http://www.mew-europe.com/.. en_ds_61020_0002.pdf

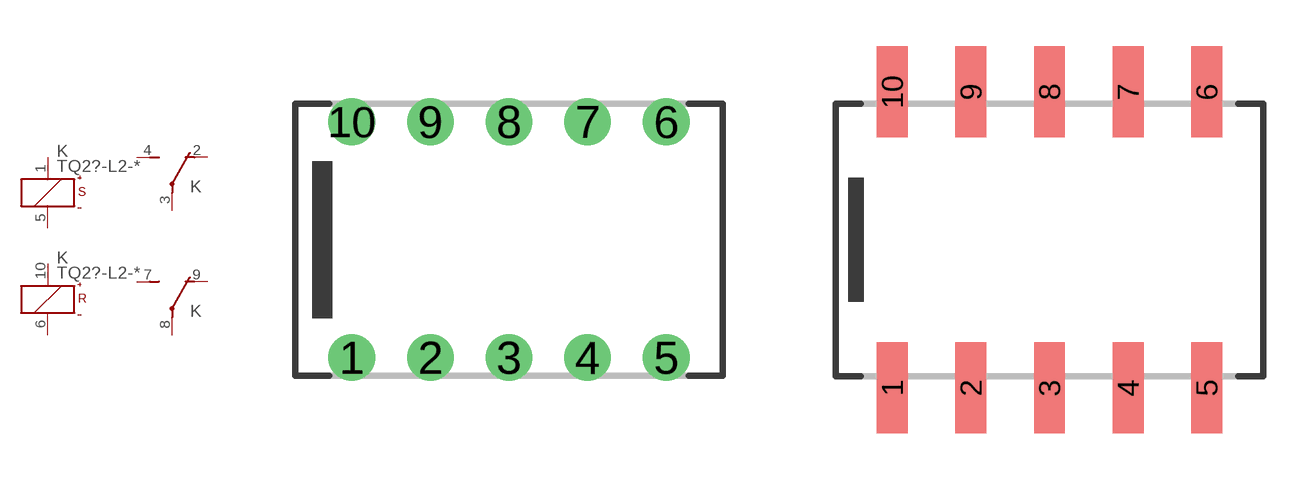
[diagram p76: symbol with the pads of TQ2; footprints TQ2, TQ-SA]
Designator prefix K; gates S=K+-S R=K+-R 1=U 2=U

## TQ2-L2-  [TQ2]
1  S:+  pas
2  1:O  pas
3  1:P  pas
4  1:S  pas
5  S:-  pas
6  R:-  pas
7  2:S  pas
8  2:P  pas
9  2:O  pas
10  R:+  pas

## TQ2SA-L2-1.5V, TQ2SA-L2-12V, TQ2SA-L2-24V, TQ2SA-L2-3V, TQ2SA-L2-4.5V, TQ2SA-L2-5V, TQ2SA-L2-6V, TQ2SA-L2-9V  [TQ-SA]
Pads as for TQ2

## TQ2SL-L2-1.5V, TQ2SL-L2-12V, TQ2SL-L2-24V, TQ2SL-L2-3V, TQ2SL-L2-4.5V, TQ2SL-L2-5V, TQ2SL-L2-6V, TQ2SL-L2-9V  [TQ-SL]
Pads as for TQ2

## TQ2SS-L2-1.5V, TQ2SS-L2-12V, TQ2SS-L2-24V, TQ2SS-L2-3V, TQ2SS-L2-4.5V, TQ2SS-L2-5V, TQ2SS-L2-6V, TQ2SS-L2-9V  [TQ-SS]
Pads as for TQ2

## Footprint TQ2 (pad centres in mm)
LOW PROFILE 2 FORM C RELAY NAiS Source: http://www.mew-europe.com/.. en_ds_61020_0001.pdf
drill 1 round: 1 -5.08,-3.81; 2 -2.54,-3.81; 3 0,-3.81; 4 2.54,-3.81; 5 5.08,-3.81; 6 5.08,3.81; 7 2.54,3.81; 8 0,3.81; 9 -2.54,3.81; 10 -5.08,3.81

## Footprint TQ-SA (pad centres in mm)
LOW-PROFILE TQ-SMD RELAYS NAiS Source: http://www.mew-europe.com/.. en_ds_61021_0004.pdf
smd 1 x 2.94: 1 -5.08,-4.78; 2 -2.54,-4.78; 3 0,-4.78; 4 2.54,-4.78; 5 5.08,-4.78; 6 5.08,4.78; 7 2.54,4.78; 8 0,4.78; 9 -2.54,4.78; 10 -5.08,4.78

## Footprint TQ-SL (pad centres in mm)
LOW-PROFILE TQ-SMD RELAYS NAiS Source: http://www.mew-europe.com/.. en_ds_61021_0004.pdf
smd 1 x 2.94: 1 -5.08,-4.78; 2 -2.54,-4.78; 3 0,-4.78; 4 2.54,-4.78; 5 5.08,-4.78; 6 5.08,4.78; 7 2.54,4.78; 8 0,4.78; 9 -2.54,4.78; 10 -5.08,4.78

## Footprint TQ-SS (pad centres in mm)
LOW-PROFILE TQ-SMD RELAYS NAiS Source: http://www.mew-europe.com/.. en_ds_61021_0004.pdf
smd 1 x 1.84: 1 -5.08,-4.23; 2 -2.54,-4.23; 3 0,-4.23; 4 2.54,-4.23; 5 5.08,-4.23; 6 5.08,4.23; 7 2.54,4.23; 8 0,4.23; 9 -2.54,4.23; 10 -5.08,4.23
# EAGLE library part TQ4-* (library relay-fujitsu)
LOW PROFILE 2 FORM C RELAY NAiS Source: http://www.mew-europe.com/.. en_ds_61020_0001.pdf

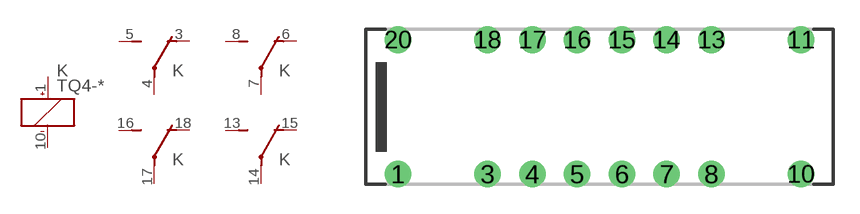
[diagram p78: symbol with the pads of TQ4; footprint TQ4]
Designator prefix K; gates _=K+- 1=U 2=U 3=U 4=U

## TQ4-12C, TQ4-24V, TQ4-3V, TQ4-4.5V, TQ4-48V, TQ4-5V, TQ4-6V, TQ4-9V  [TQ4]
1  _:+  pas
3  1:O  pas
4  1:P  pas
5  1:S  pas
6  2:O  pas
7  2:P  pas
8  2:S  pas
10  _:-  pas
13  4:S  pas
14  4:P  pas
15  4:O  pas
16  3:S  pas
17  3:P  pas
18  3:O  pas

## TQ4-12VL-, TQ4-24VL-, TQ4-3VL-, TQ4-4.5VL-, TQ4-5VL-, TQ4-6VL-, TQ4-9VL-  [TQ4]
1  _:-  pas
3  1:O  pas
4  1:P  pas
5  1:S  pas
6  2:O  pas
7  2:P  pas
8  2:S  pas
10  _:+  pas
13  4:S  pas
14  4:P  pas
15  4:O  pas
16  3:S  pas
17  3:P  pas
18  3:O  pas

## Footprint TQ4 (pad centres in mm)
LOW PROFILE 2 FORM C RELAY NAiS Source: http://www.mew-europe.com/.. en_ds_61020_0001.pdf
drill 1 round: 1 -11.43,-3.81; 3 -6.35,-3.81; 4 -3.81,-3.81; 5 -1.27,-3.81; 6 1.27,-3.81; 7 3.81,-3.81; 8 6.35,-3.81; 10 11.43,-3.81; 11 11.43,3.81; 13 6.35,3.81; 14 3.81,3.81; 15 1.27,3.81; 16 -1.27,3.81; 17 -3.81,3.81; 18 -6.35,3.81; 20 -11.43,3.81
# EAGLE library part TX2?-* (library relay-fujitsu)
2 AMP. HIGH CAPACITY RELAY NAiS WITH HIGH SURGE VOLTAGE & HIGH BREAKDOWN VOLTAGE Source: http://www.mew-europe.com/.. en_ds_61022_0001.pdf

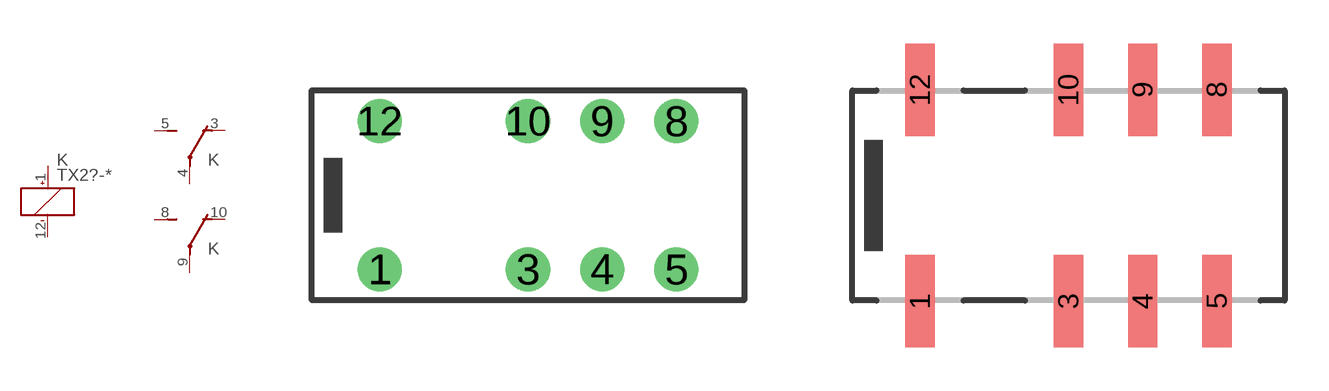
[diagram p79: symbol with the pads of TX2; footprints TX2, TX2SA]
Designator prefix K; gates _=K+- 1=U 2=U

## TX2-1.5V, TX2-12V, TX2-24V, TX2-3V, TX2-4.5V, TX2-5V, TX2-6V, TX2-9V  [TX2]
1  _:+  pas
3  1:O  pas
4  1:P  pas
5  1:S  pas
8  2:S  pas
9  2:P  pas
10  2:O  pas
12  _:-  pas

## TX2SA-1.5V, TX2SA-12V, TX2SA-24V, TX2SA-3V, TX2SA-4.5V, TX2SA-48V, TX2SA-5V, TX2SA-6V, TX2SA-9V  [TX2SA]
Pads as for TX2

## TX2-L-1.5V, TX2-L-12V, TX2-L-24V, TX2-L-3V, TX2-L-4.5V, TX2-L-5V, TX2-L-6V, TX2-L-9V  [TX2]
1  _:-  pas
3  1:O  pas
4  1:P  pas
5  1:S  pas
8  2:S  pas
9  2:P  pas
10  2:O  pas
12  _:+  pas

## TX2SL-1.5V, TX2SL-12V, TX2SL-24V, TX2SL-3V, TX2SL-4.5V, TX2SL-48V, TX2SL-5V, TX2SL-6V, TX2SL-9V  [TX2SL]
Pads as for TX2

## TX2SS-1.5V, TX2SS-12V, TX2SS-24V, TX2SS-3V, TX2SS-4.5V, TX2SS-48V, TX2SS-5V, TX2SS-6V, TX2SS-9V  [TX2SS]
Pads as for TX2

## TX2SA-L-1.5V, TX2SA-L-12V, TX2SA-L-24V, TX2SA-L-3V, TX2SA-L-4.5V, TX2SA-L-5V, TX2SA-L-6V, TX2SA-L-9V  [TX2SA]
Pads as for TX2

## TX2SL-L-1.5V, TX2SL-L-12V, TX2SL-L-24V, TX2SL-L-3V, TX2SL-L-4.5V, TX2SL-L-5V, TX2SL-L-6V, TX2SL-L-9V  [TX2SL]
Pads as for TX2

## TX2SS-L-1.5V, TX2SS-L-12V, TX2SS-L-24V, TX2SS-L-3V, TX2SS-L-4.5V, TX2SS-L-5V, TX2SS-L-6V, TX2SS-L-9V  [TX2SS]
Pads as for TX2

## Footprint TX2 (pad centres in mm)
2 AMP. HIGH CAPACITY RELAY NAiS WITH HIGH SURGE VOLTAGE & HIGH BREAKDOWN VOLTAGE Source: http://www.mew-europe.com/.. en_ds_61022_0001.pdf
drill 1 round: 1 -5.08,-2.54; 3 0,-2.54; 4 2.54,-2.54; 5 5.08,-2.54; 8 5.08,2.54; 9 2.54,2.54; 10 0,2.54; 12 -5.08,2.54

## Footprint TX2SA (pad centres in mm)
2 AMP. HIGH CAPACITY RELAY NAiS WITH HIGH SURGE VOLTAGE & HIGH BREAKDOWN VOLTAGE Source: http://www.mew-europe.com/.. en_ds_61022_0001.pdf
smd 1 x 3.16: 1 -5.08,-3.62; 3 0,-3.62; 4 2.54,-3.62; 5 5.08,-3.62; 8 5.08,3.62; 9 2.54,3.62; 10 0,3.62; 12 -5.08,3.62

## Footprint TX2SL (pad centres in mm)
2 AMP. HIGH CAPACITY RELAY NAiS WITH HIGH SURGE VOLTAGE & HIGH BREAKDOWN VOLTAGE Source: http://www.mew-europe.com/.. en_ds_61022_0001.pdf
smd 1 x 3.16: 1 -5.08,-3.62; 3 0,-3.62; 4 2.54,-3.62; 5 5.08,-3.62; 8 5.08,3.62; 9 2.54,3.62; 10 0,3.62; 12 -5.08,3.62

## Footprint TX2SS (pad centres in mm)
2 AMP. HIGH CAPACITY RELAY NAiS WITH HIGH SURGE VOLTAGE & HIGH BREAKDOWN VOLTAGE Source: http://www.mew-europe.com/.. en_ds_61022_0001.pdf
smd 1 x 2.16: 1 -5.08,-3.12; 3 0,-3.12; 4 2.54,-3.12; 5 5.08,-3.12; 8 5.08,3.12; 9 2.54,3.12; 10 0,3.12; 12 -5.08,3.12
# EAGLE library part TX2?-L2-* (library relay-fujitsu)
TX Relay 2 coil latching NAiS 2 AMP. HIGH CAPACITY RELAY WITH HIGH SURGE VOLTAGE & HIGH BREAKDOWN VOLTAGE Source: http://www.mew-europe.com/.. en_ds_61022_0001.pdf TX-S SMALL POLARIZED WITH HIGH SENSITIVITY 50mW Source: http://www.mew-europe.com/.. en_ds_61022_0022.pdf

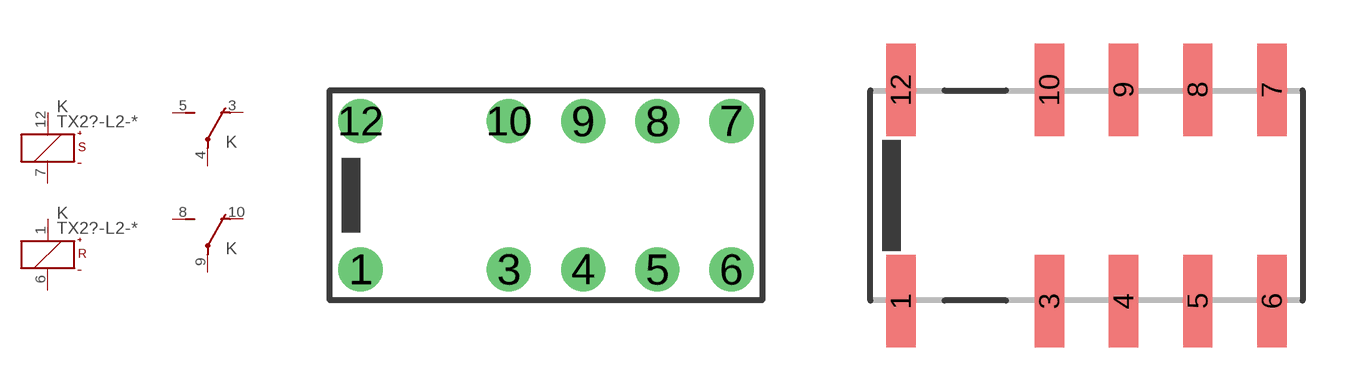
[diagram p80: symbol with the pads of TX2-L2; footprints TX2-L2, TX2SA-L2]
Designator prefix K; gates S=K+-S R=K+-R 1=U 2=U

## TX2-L2-1.5V, TX2-L2-12V, TX2-L2-24V, TX2-L2-3V, TX2-L2-4.5V, TX2-L2-5V, TX2-L2-6V, TX2-L2-9V  [TX2-L2]
1  R:+  pas
3  1:O  pas
4  1:P  pas
5  1:S  pas
6  R:-  pas
7  S:-  pas
8  2:S  pas
9  2:P  pas
10  2:O  pas
12  S:+  pas

## TX2SA-L2-1.5V, TX2SA-L2-12V, TX2SA-L2-24V, TX2SA-L2-3V, TX2SA-L2-4.5V, TX2SA-L2-5V, TX2SA-L2-6V, TX2SA-L2-9V  [TX2SA-L2]
Pads as for TX2-L2

## TX2SL-L2-1.5V, TX2SL-L2-12V, TX2SL-L2-24V, TX2SL-L2-3V, TX2SL-L2-4.5V, TX2SL-L2-5V, TX2SL-L2-6V, TX2SL-L2-9V  [TX2SL-L2]
Pads as for TX2-L2

## TX2SS-L2-1.5V, TX2SS-L2-12V, TX2SS-L2-24V, TX2SS-L2-3V, TX2SS-L2-4.5V, TX2SS-L2-5V, TX2SS-L2-6V, TX2SS-L2-9V  [TX2SS-L2]
Pads as for TX2-L2

## TX2S2SA-L2-1.5V, TX2S2SA-L2-12V, TX2S2SA-L2-24V, TX2S2SA-L2-3V, TX2S2SA-L2-4.5V, TX2S2SA-L2-5V, TX2S2SA-L2-6V, TX2S2SA-L2-9V  [TX2SA-L2]
Pads as for TX2-L2

## TX2S2SL-L2-  [TX2SL-L2]
Pads as for TX2-L2

## TX2S2SS-L2-  [TX2SS-L2]
Pads as for TX2-L2

## Footprint TX2-L2 (pad centres in mm)
2 AMP. HIGH CAPACITY RELAY NAiS WITH HIGH SURGE VOLTAGE & HIGH BREAKDOWN VOLTAGE 2 coil latching Source: http://www.mew-europe.com/.. en_ds_61022_0001.pdf
drill 1 round: 1 -6.35,-2.54; 3 -1.27,-2.54; 4 1.27,-2.54; 5 3.81,-2.54; 6 6.35,-2.54; 7 6.35,2.54; 8 3.81,2.54; 9 1.27,2.54; 10 -1.27,2.54; 12 -6.35,2.54

## Footprint TX2SA-L2 (pad centres in mm)
2 AMP. HIGH CAPACITY RELAY NAiS WITH HIGH SURGE VOLTAGE & HIGH BREAKDOWN VOLTAGE 2 coil latching Source: http://www.mew-europe.com/.. en_ds_61022_0001.pdf
smd 1 x 3.16: 1 -6.35,-3.62; 3 -1.27,-3.62; 4 1.27,-3.62; 5 3.81,-3.62; 6 6.35,-3.62; 7 6.35,3.62; 8 3.81,3.62; 9 1.27,3.62; 10 -1.27,3.62; 12 -6.35,3.62

## Footprint TX2SL-L2 (pad centres in mm)
2 AMP. HIGH CAPACITY RELAY NAiS WITH HIGH SURGE VOLTAGE & HIGH BREAKDOWN VOLTAGE 2 coil latching Source: http://www.mew-europe.com/.. en_ds_61022_0001.pdf
smd 1 x 3.16: 1 -6.35,-3.62; 3 -1.27,-3.62; 4 1.27,-3.62; 5 3.81,-3.62; 6 6.35,-3.62; 7 6.35,3.62; 8 3.81,3.62; 9 1.27,3.62; 10 -1.27,3.62; 12 -6.35,3.62

## Footprint TX2SS-L2 (pad centres in mm)
2 AMP. HIGH CAPACITY RELAY NAiS WITH HIGH SURGE VOLTAGE & HIGH BREAKDOWN VOLTAGE 2 coil latching Source: http://www.mew-europe.com/.. en_ds_61022_0001.pdf
smd 1 x 2.16: 1 -6.35,-3.12; 3 -1.27,-3.12; 4 1.27,-3.12; 5 3.81,-3.12; 6 6.35,-3.12; 7 6.35,3.12; 8 3.81,3.12; 9 1.27,3.12; 10 -1.27,3.12; 12 -6.35,3.12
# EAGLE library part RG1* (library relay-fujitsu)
HIGH FREQUENCY RELAYS WITH 1C AND 2C CONTACTS NAiS Source: http://www.mew-europe.com/.. en_ds_61302_0000.pdf

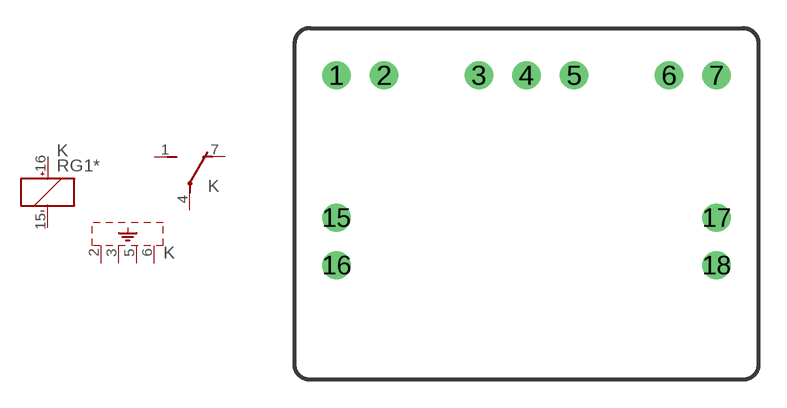
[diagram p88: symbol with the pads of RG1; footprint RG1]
Designator prefix K; gates G$1=K+- G$2=U G$3=SHIELD-4

## RG1-12V, RG1-24V, RG1-3V, RG1-48V, RG1-5V, RG1-6V, RG1-9V, RG1T-12V, RG1T-24V, RG1T-3V, RG1T-48V, RG1T-5V, RG1T-6V, RG1T-9V  [RG1]
1  G$2:S  pas
2  G$3:SH  pas
3  G$3:SH  pas
4  G$2:P  pas
5  G$3:SH  pas
6  G$3:SH  pas
7  G$2:O  pas
15  G$1:-  pas
16  G$1:+  pas

## RG1-L, RG1-12V-L, RG1-24V-L, RG1-3V-L, RG1-48V-L, RG1-5V-L, RG1-6V-L, RG1-9V-L  [RG1]
1  G$2:S  pas
2  G$3:SH  pas
3  G$3:SH  pas
4  G$2:P  pas
5  G$3:SH  pas
6  G$3:SH  pas
7  G$2:O  pas
15  G$1:+  pas
16  G$1:-  pas

## RG1-12VT-L, RG1-24VT-L, RG1-3VT-L, RG1-48VT-L, RG1-5VT-L, RG1-6VT-L, RG1-9VT-L  [RG1]
Pads as for RG1

## Footprint RG1 (pad centres in mm)
HIGH FREQUENCY RELAYS WITH 1C AND 2C CONTACTS NAiS Source: http://www.mew-europe.com/.. en_ds_61302_0000.pdf
drill 1 round: 1 -10.16,7.62; 2 -7.62,7.62; 3 -2.54,7.62; 4 0,7.62; 5 2.54,7.62; 6 7.62,7.62; 7 10.16,7.62; 15 -10.16,0; 16 -10.16,-2.54; 17 10.16,0; 18 10.16,-2.54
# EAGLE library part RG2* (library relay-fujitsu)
HIGH FREQUENCY RELAYS WITH 1C AND 2C CONTACTS NAiS Source: http://www.mew-europe.com/.. en_ds_61302_0000.pdf

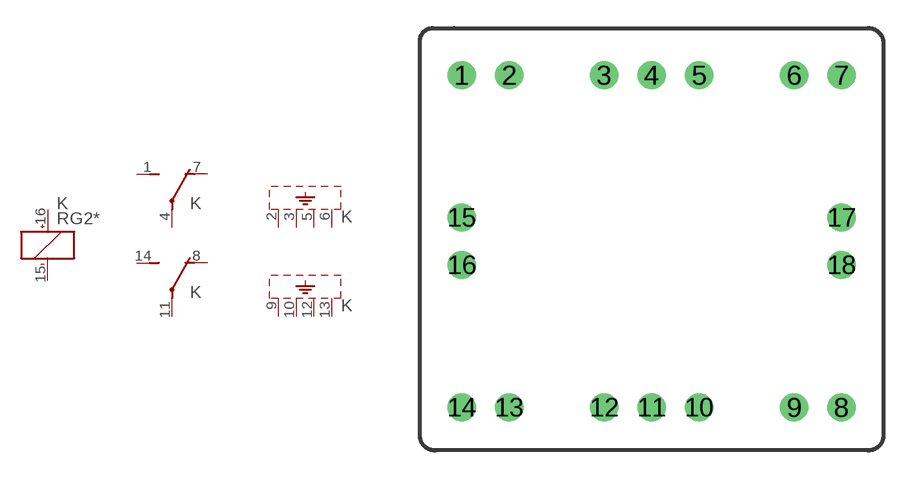
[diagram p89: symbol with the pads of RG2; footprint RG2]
Designator prefix K; gates A=K+- 1=U 2=U S1=SHIELD-4 S2=SHIELD-4

## RG2-12V, RG2-24V, RG2-3V, RG2-48V, RG2-5V, RG2-6V, RG2-9V, RG2T-12V, RG2T-24V, RG2T-3V, RG2T-48V, RG2T-5V, RG2T-6V, RG2T-9V  [RG2]
1  1:S  pas
2  S1:SH  pas
3  S1:SH  pas
4  1:P  pas
5  S1:SH  pas
6  S1:SH  pas
7  1:O  pas
8  2:O  pas
9  S2:SH  pas
10  S2:SH  pas
11  2:P  pas
12  S2:SH  pas
13  S2:SH  pas
14  2:S  pas
15  A:-  pas
16  A:+  pas

## RG2-12V-L, RG2-24V-L, RG2-3V-L, RG2-48V-L, RG2-5V-L, RG2-6V-L, RG2-9V-L  [RG2]
1  1:S  pas
2  S1:SH  pas
3  S1:SH  pas
4  1:P  pas
5  S1:SH  pas
6  S1:SH  pas
7  1:O  pas
8  2:O  pas
9  S2:SH  pas
10  S2:SH  pas
11  2:P  pas
12  S2:SH  pas
13  S2:SH  pas
14  2:S  pas
15  A:+  pas
16  A:-  pas

## RG2-12VT-L, RG2-24VT-L, RG2-3VT-L, RG2-48VT-L, RG2-5VT-L, RG2-6VT-L, RG2-9VT-L  [RG2]
Pads as for RG2

## Footprint RG2 (pad centres in mm)
HIGH FREQUENCY RELAYS WITH 1C AND 2C CONTACTS NAiS Source: http://www.mew-europe.com/.. en_ds_61302_0000.pdf
drill 1 round: 1 -10.16,8.89; 2 -7.62,8.89; 3 -2.54,8.89; 4 0,8.89; 5 2.54,8.89; 6 7.62,8.89; 7 10.16,8.89; 8 10.16,-8.89; 9 7.62,-8.89; 10 2.54,-8.89; 11 0,-8.89; 12 -2.54,-8.89; 13 -7.62,-8.89; 14 -10.16,-8.89; 15 -10.16,1.27; 16 -10.16,-1.27; 17 10.16,1.27; 18 10.16,-1.27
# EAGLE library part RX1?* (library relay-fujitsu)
SMALL MICRO WAVE RELAY NAiS Source: http://www.mew-europe.com/.. en_ds_61307_0000.pdf

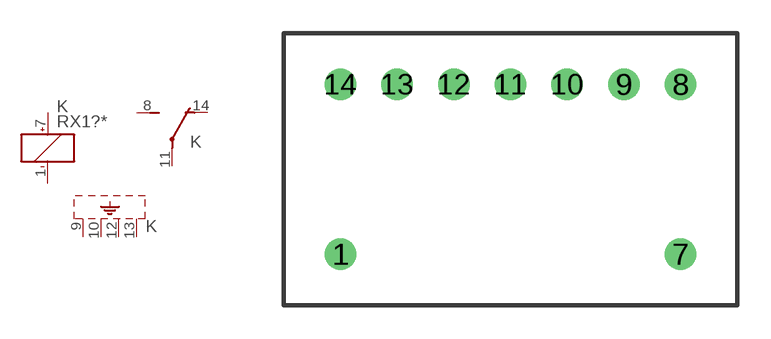
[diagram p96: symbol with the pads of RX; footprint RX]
Designator prefix K; gates 1=K+- 2=U 3=SHIELD-4

## RX10003, RX10006, RX1000H, RX10012, RX10024, RX1004H  [RX]
1  1:-  pas
7  1:+  pas
8  2:S  pas
9  3:SH  pas
10  3:SH  pas
11  2:P  pas
12  3:SH  pas
13  3:SH  pas
14  2:O  pas

## RX11003, RX11006, RX11009, RX11012, RX11024, RX1104H  [RX]
1  1:+  pas
7  1:-  pas
8  2:S  pas
9  3:SH  pas
10  3:SH  pas
11  2:P  pas
12  3:SH  pas
13  3:SH  pas
14  2:O  pas

## Footprint RX (pad centres in mm)
SMALL MICRO WAVE RELAY NAiS Source: http://www.mew-europe.com/.. en_ds_61307_0000.pdf
drill 0.9 round: 1 -7.62,-3.81; 7 7.62,-3.81; 8 7.62,3.81; 9 5.08,3.81; 10 2.54,3.81; 11 0,3.81; 12 -2.54,3.81; 13 -5.08,3.81; 14 -7.62,3.81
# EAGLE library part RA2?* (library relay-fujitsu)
MICROWAVE RELAY FOR ATTENUATOR CIRCUIT NAiS Source: http://www.mew-europe.com/.. en_ds_61308_0000.pdf

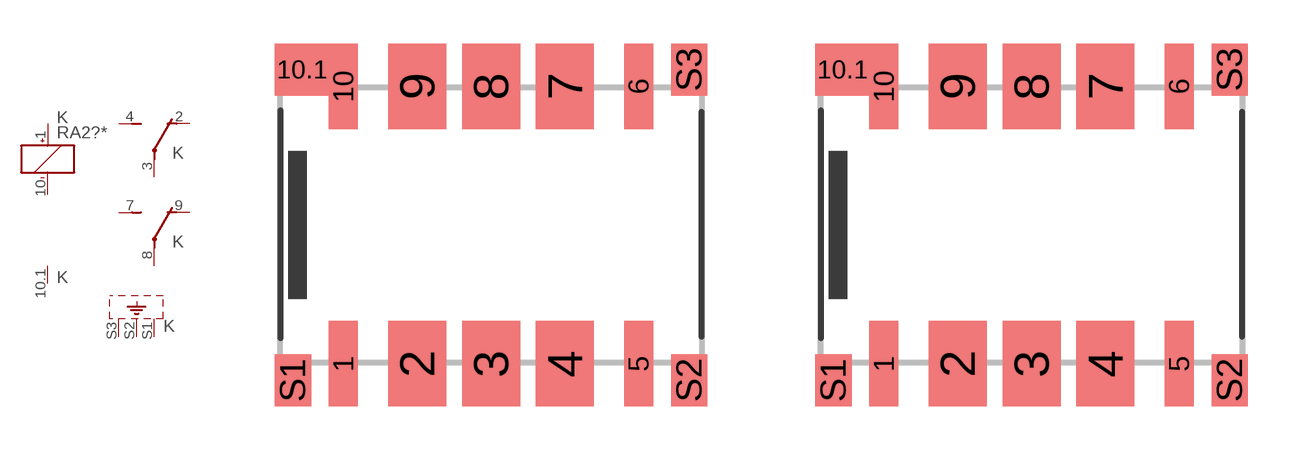
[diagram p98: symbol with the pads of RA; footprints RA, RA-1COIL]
Designator prefix K; gates 1=K+- 2=U 3=U 4=K-PIN S1=SHIELD-3

## RA200A03, RA200A05, RA200A06, RA200A09, RA200A12, RA200A1H, RA200A24, RA200A48, RA200A4V  [RA]
1  1:+  pas
2  2:O  pas
3  2:P  pas
4  2:S  pas
7  3:S  pas
8  3:P  pas
9  3:O  pas
10  1:-  pas
10.1  4:-  pas
S1  S1:SH  pas
S2  S1:SH  pas
S3  S1:SH  pas

## RA210A03, RA210A05, RA210A06, RA210A09, RA210A12, RA210A1H, RA210A24, RA210A4H  [RA-1COIL]
1  1:-  pas
2  2:O  pas
3  2:P  pas
4  2:S  pas
7  3:S  pas
8  3:P  pas
9  3:O  pas
10  1:+  pas
10.1  4:-  pas
S1  S1:SH  pas
S2  S1:SH  pas
S3  S1:SH  pas

## Footprint RA (pad centres in mm)
MICROWAVE RELAY FOR ATTENUATOR CIRCUIT NAiS Source: http://www.mew-europe.com/.. en_ds_61308_0000.pdf
smd 1 x 2.94: 1 -5.08,-4.78; 5 5.08,-4.78; 6 5.08,4.78; 10 -5.08,4.78
smd 2 x 2.94: 2 -2.54,-4.78; 3 0,-4.78; 4 2.54,-4.78; 7 2.54,4.78; 8 0,4.78; 9 -2.54,4.78
smd 1.9 x 1.8: 10.1 -6.5,5.35
smd 1.25 x 1.8: S1 -6.82,-5.35; S2 6.82,-5.35; S3 6.82,5.35

## Footprint RA-1COIL (pad centres in mm)
MICROWAVE RELAY FOR ATTENUATOR CIRCUIT NAiS Source: http://www.mew-europe.com/.. en_ds_61308_0000.pdf
smd 1 x 2.94: 1 -5.08,-4.78; 5 5.08,-4.78; 6 5.08,4.78; 10 -5.08,4.78
smd 2 x 2.94: 2 -2.54,-4.78; 3 0,-4.78; 4 2.54,-4.78; 7 2.54,4.78; 8 0,4.78; 9 -2.54,4.78
smd 1.9 x 1.8: 10.1 -6.5,5.35
smd 1.25 x 1.8: S1 -6.82,-5.35; S2 6.82,-5.35; S3 6.82,5.35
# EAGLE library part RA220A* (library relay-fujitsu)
MICROWAVE RELAY FOR ATTENUATOR CIRCUIT NAiS Source: http://www.mew-europe.com/.. en_ds_61308_0000.pdf

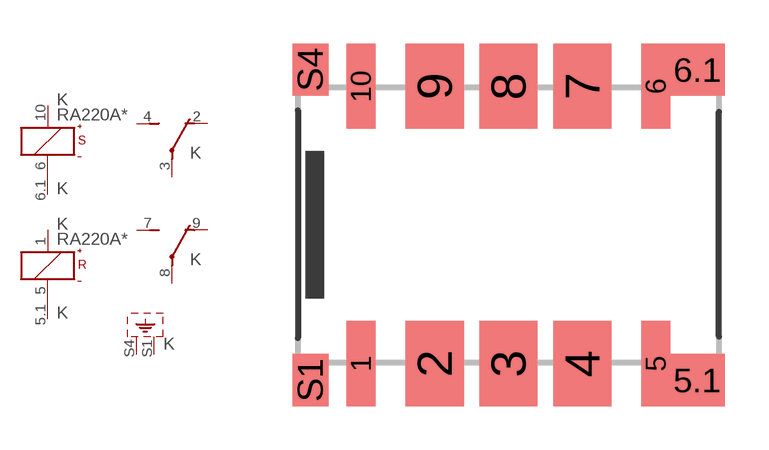
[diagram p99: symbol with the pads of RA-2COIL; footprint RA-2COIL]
Designator prefix K; gates S=K+-S R=K+-R 1=U 2=U SH=SHIELD-2 P5=K-PIN P6=K-PIN

## RA220A03, RA220A05, RA220A06, RA220A09, RA220A12, RA220A1H, RA220A24, RA220A4H  [RA-2COIL]
1  R:+  pas
2  1:O  pas
3  1:P  pas
4  1:S  pas
5  R:-  pas
5.1  P5:-  pas
6  S:-  pas
6.1  P6:-  pas
7  2:S  pas
8  2:P  pas
9  2:O  pas
10  S:+  pas
S1  SH:SH  pas
S4  SH:SH  pas

## Footprint RA-2COIL (pad centres in mm)
MICROWAVE RELAY FOR ATTENUATOR CIRCUIT NAiS Source: http://www.mew-europe.com/.. en_ds_61308_0000.pdf
smd 1 x 2.94: 1 -5.08,-4.78; 5 5.08,-4.78; 6 5.08,4.78; 10 -5.08,4.78
smd 2 x 2.94: 2 -2.54,-4.78; 3 0,-4.78; 4 2.54,-4.78; 7 2.54,4.78; 8 0,4.78; 9 -2.54,4.78
smd 1.9 x 1.8: 5.1 6.5,-5.35; 6.1 6.51,5.35
smd 1.25 x 1.8: S1 -6.82,-5.35; S4 -6.82,5.35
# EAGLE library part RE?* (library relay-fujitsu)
SMALL MICROWAVE RELAYS FOR BROADCASTING INDUSTRY NAiS Source: http://www.mew-europe.com/.. en_ds_61310_0000.pdf

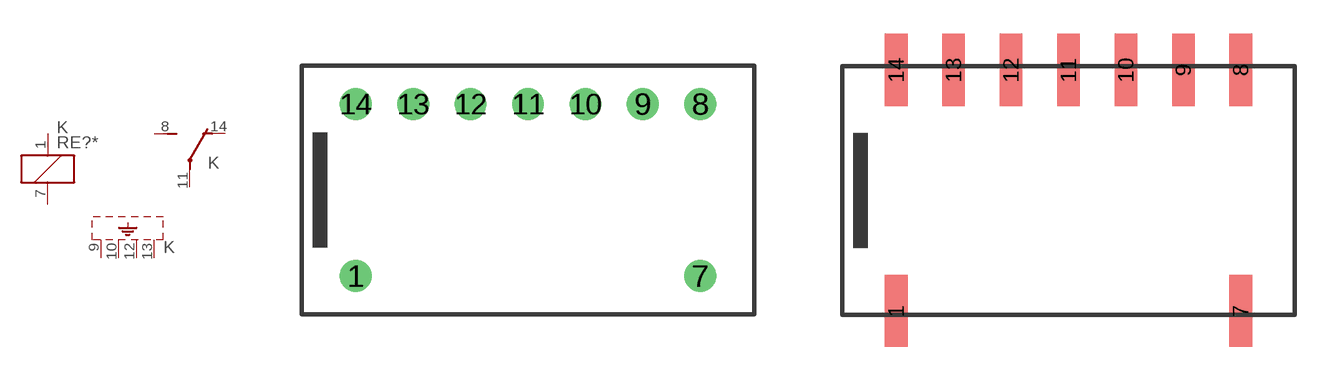
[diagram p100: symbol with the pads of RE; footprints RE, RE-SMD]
Designator prefix K; gates 1=K 2=U S1=SHIELD-4

## RE1303, RE1306, RE1309, RE1312, RE1324, RE134H  [RE]
1  1:1  pas
7  1:2  pas
8  2:S  pas
9  S1:SH  pas
10  S1:SH  pas
11  2:P  pas
12  S1:SH  pas
13  S1:SH  pas
14  2:O  pas

## RE13A03, RE13A06, RE13A09, RE13A12, RE13A24, RE13A4H  [RE-SMD]
Pads as for RE

## Footprint RE (pad centres in mm)
SMALL MICROWAVE RELAYS FOR BROADCASTING INDUSTRY NAiS Source: http://www.mew-europe.com/.. en_ds_61310_0000.pdf
drill 0.9 round: 1 -7.62,-3.81; 7 7.62,-3.81; 8 7.62,3.81; 9 5.08,3.81; 10 2.54,3.81; 11 0,3.81; 12 -2.54,3.81; 13 -5.08,3.81; 14 -7.62,3.81

## Footprint RE-SMD (pad centres in mm)
SMALL MICROWAVE RELAYS FOR BROADCASTING INDUSTRY NAiS Source: http://www.mew-europe.com/.. en_ds_61310_0000.pdf
smd 1 x 3.2: 1 -7.62,-5.334; 7 7.62,-5.334; 8 7.62,5.334; 9 5.08,5.334; 10 2.54,5.334; 11 0,5.334; 12 -2.54,5.334; 13 -5.08,5.334; 14 -7.62,5.334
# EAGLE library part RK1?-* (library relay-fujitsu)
1.5 GHz MICROWAVE RELAY NAiS Source: http://www.mew-europe.com/.. en_ds_61311_0000.pdf

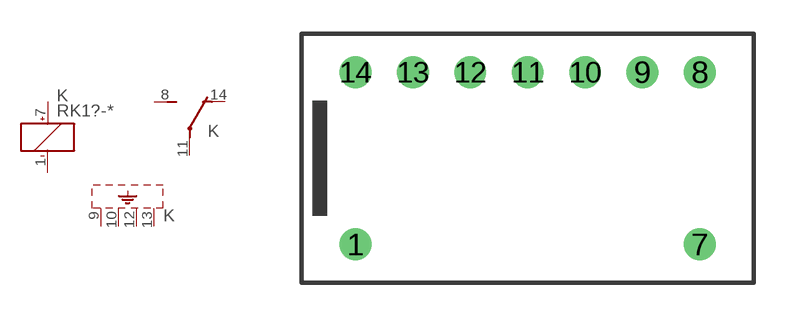
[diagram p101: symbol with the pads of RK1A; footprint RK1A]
Designator prefix K; gates 1=K+- 2=U S=SHIELD-4

## RK1-12V, RK1-24, RK1-3V, RK1-4.5V, RK1-5V, RK1-6V, RK1-9V  [RK1A]
1  1:-  pas
7  1:+  pas
8  2:S  pas
9  S:SH  pas
10  S:SH  pas
11  2:P  pas
12  S:SH  pas
13  S:SH  pas
14  2:O  pas

## RK1R-12V, RK1R-24V, RK1R-3V, RK1R-4.5V, RK1R-5V, RK1R-6V, RK1R-9V  [RK1A]
1  1:-  pas
7  1:+  pas
8  2:O  pas
9  S:SH  pas
10  S:SH  pas
11  2:P  pas
12  S:SH  pas
13  S:SH  pas
14  2:S  pas

## RK1-L-12V, RK1-L-24V, RK1-L-3V, RK1-L-4.5V, RK1-L-5V, RK1-L-6V, RK1-L-9V  [RK1A]
1  1:+  pas
7  1:-  pas
8  2:S  pas
9  S:SH  pas
10  S:SH  pas
11  2:P  pas
12  S:SH  pas
13  S:SH  pas
14  2:O  pas

## RK1R-L-12V, RK1R-L-24V, RK1R-L-3V, RK1R-L-4.5V, RK1R-L-5V, RK1R-L-6V, RK1R-L-9V  [RK1A]
1  1:+  pas
7  1:-  pas
8  2:O  pas
9  S:SH  pas
10  S:SH  pas
11  2:P  pas
12  S:SH  pas
13  S:SH  pas
14  2:S  pas

## Footprint RK1A (pad centres in mm)
1.5 GHz MICROWAVE RELAY NAiS Source: http://www.mew-europe.com/.. en_ds_61311_0000.pdf
drill 0.9 round: 1 -7.62,-3.81; 7 7.62,-3.81; 8 7.62,3.81; 9 5.08,3.81; 10 2.54,3.81; 11 0,3.81; 12 -2.54,3.81; 13 -5.08,3.81; 14 -7.62,3.81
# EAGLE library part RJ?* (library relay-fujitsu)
SMD RELAYS WITH 5GHz CAPABILITIES NAiS Source: http://www.mew-europe.com/.. en_ds_61313_0000.pdf

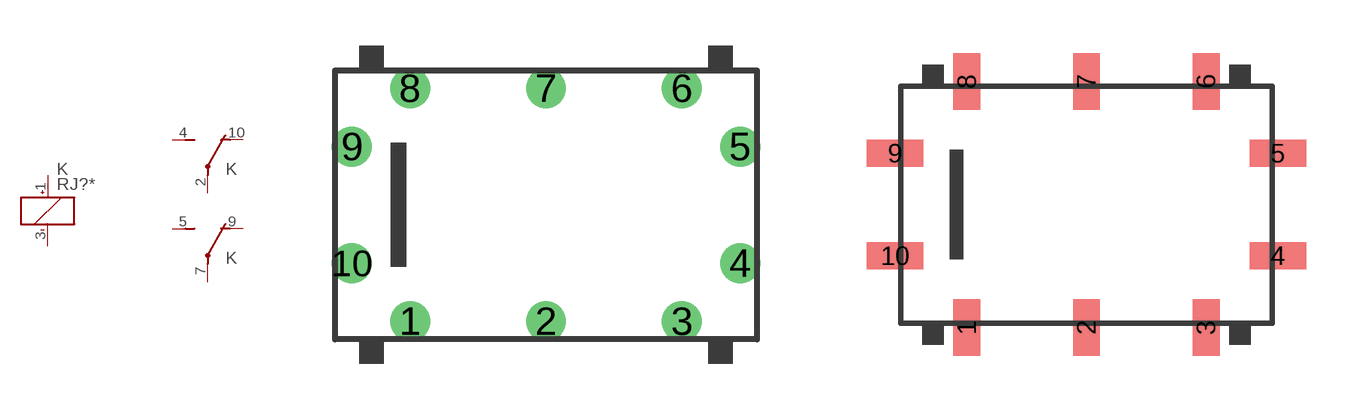
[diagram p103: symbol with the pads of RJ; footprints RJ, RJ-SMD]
Designator prefix K; gates 1=K+- 2=U 3=U

## RJ2003, RJ2012, RJ2024, RJ204H  [RJ]
1  1:+  pas
2  2:P  pas
3  1:-  pas
4  2:S  pas
5  3:S  pas
7  3:P  pas
9  3:O  pas
10  2:O  pas

## RJ20A03, RJ20A12, RJ20A24, RJ20A4H  [RJ-SMD]
Pads as for RJ

## Footprint RJ (pad centres in mm)
SMD RELAYS WITH 5GHz CAPABILITIES NAiS Source: http://www.mew-europe.com/.. en_ds_61313_0000.pdf
drill 0.8 round: 1 -4.445,-3.81; 2 0,-3.81; 3 4.445,-3.81; 4 6.35,-1.905; 5 6.35,1.905; 6 4.445,3.81; 7 0,3.81; 8 -4.445,3.81; 9 -6.35,1.905; 10 -6.35,-1.905

## Footprint RJ-SMD (pad centres in mm)
SMD RELAYS WITH 5GHz CAPABILITIES NAiS Source: http://www.mew-europe.com/.. en_ds_61313_0000.pdf
smd 1 x 2.1: 1 -4.445,-4.572; 2 0,-4.572; 3 4.445,-4.572; 6 4.445,4.572; 7 0,4.572; 8 -4.445,4.572
smd 2.1 x 1: 4 7.112,-1.905; 5 7.112,1.905; 9 -7.112,1.905; 10 -7.112,-1.905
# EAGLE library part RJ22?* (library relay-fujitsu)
SMD RELAYS WITH 5GHz CAPABILITIES NAiS Source: http://www.mew-europe.com/.. en_ds_61313_0000.pdf

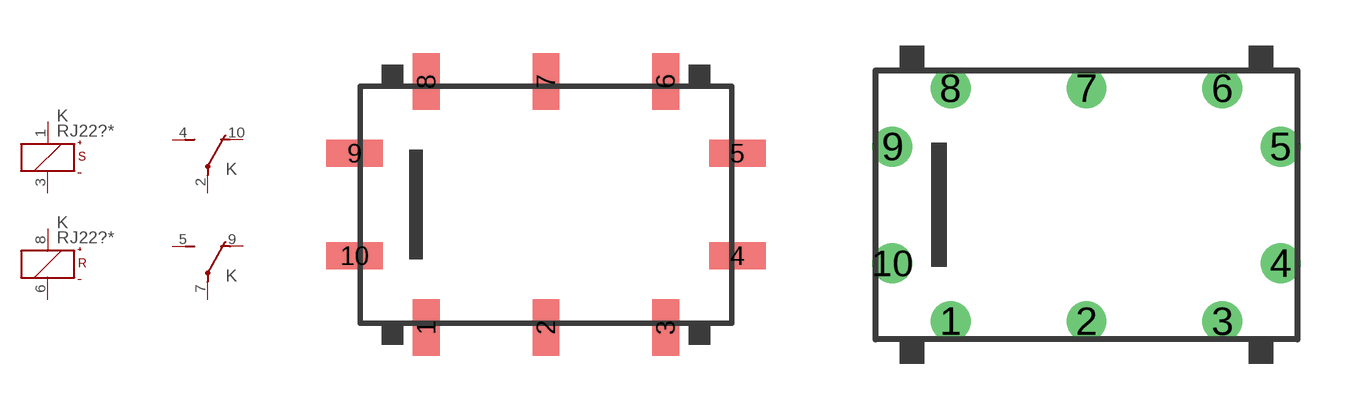
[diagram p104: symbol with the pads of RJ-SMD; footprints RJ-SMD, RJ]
Designator prefix K; gates S=K+-S R=K+-R 1=U 2=U

## RJ22A03, RJ22A12, RJ22A24, RJ22A4H  [RJ-SMD]
1  S:+  pas
2  1:P  pas
3  S:-  pas
4  1:S  pas
5  2:S  pas
6  R:-  pas
7  2:P  pas
8  R:+  pas
9  2:O  pas
10  1:O  pas

## RJ2203, RJ2212, RJ2224, RJ224H  [RJ]
Pads as for RJ-SMD

## Footprint RJ-SMD (pad centres in mm)
SMD RELAYS WITH 5GHz CAPABILITIES NAiS Source: http://www.mew-europe.com/.. en_ds_61313_0000.pdf
smd 1 x 2.1: 1 -4.445,-4.572; 2 0,-4.572; 3 4.445,-4.572; 6 4.445,4.572; 7 0,4.572; 8 -4.445,4.572
smd 2.1 x 1: 4 7.112,-1.905; 5 7.112,1.905; 9 -7.112,1.905; 10 -7.112,-1.905

## Footprint RJ (pad centres in mm)
SMD RELAYS WITH 5GHz CAPABILITIES NAiS Source: http://www.mew-europe.com/.. en_ds_61313_0000.pdf
drill 0.8 round: 1 -4.445,-3.81; 2 0,-3.81; 3 4.445,-3.81; 4 6.35,-1.905; 5 6.35,1.905; 6 4.445,3.81; 7 0,3.81; 8 -4.445,3.81; 9 -6.35,1.905; 10 -6.35,-1.905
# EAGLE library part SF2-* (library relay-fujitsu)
POLARISED, MONOSTABLE RELAY WITH FORCIBLY GUIDED CONTACTS NAiS Source: http://www.mew-europe.com/.. en_ds_61404_0001.pdf

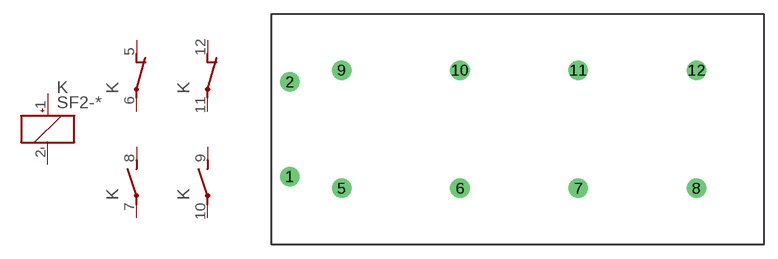
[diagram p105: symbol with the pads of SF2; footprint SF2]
Designator prefix K; gates S=K+- 1=O 2=O 3=S 4=S

## SF2-12V, SF2-18V, SF2-21V, SF2-24V, SF2-36V, SF2-48V, SF2-5V, SF2-60V, SF2-9V  [SF2]
1  S:+  pas
2  S:-  pas
5  1:O  pas
6  1:P  pas
7  3:P  pas
8  3:S  pas
9  4:S  pas
10  4:P  pas
11  2:P  pas
12  2:O  pas

## Footprint SF2 (pad centres in mm)
POLARISED, MONOSTABLE RELAY WITH FORCIBLY GUIDED CONTACTS NAiS Source: http://www.mew-europe.com/.. en_ds_61404_0001.pdf
drill 1.4 round: 1 -24.638,-5.08; 2 -24.638,5.08; 5 -19.05,-6.35; 6 -6.35,-6.35; 7 6.35,-6.35; 8 19.05,-6.35; 9 -19.05,6.35; 10 -6.35,6.35; 11 6.35,6.35; 12 19.05,6.35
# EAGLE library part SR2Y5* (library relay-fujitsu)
Safety Relay 2 pole 6 A SCHRACK Source: http://www.schrack.com/.. 5809.pdf

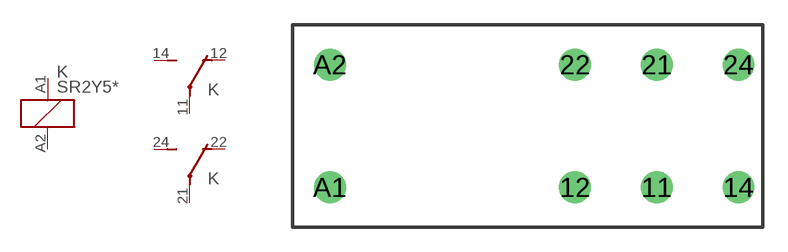
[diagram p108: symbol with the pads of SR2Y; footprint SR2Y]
Designator prefix K; gates 1=K 2=U 3=U

## SR2Y5005, SR2Y5006, SR2Y5009, SR2Y5012, SR2Y5018, SR2Y5021, SR2Y5024, SR2Y5036, SR2Y5040, SR2Y5048, SR2Y5060, SR2Y5080, SR2Y5110  [SR2Y]
11  2:P  pas
12  2:O  pas
14  2:S  pas
21  3:P  pas
22  3:O  pas
24  3:S  pas
A1  1:1  pas
A2  1:2  pas

## Footprint SR2Y (pad centres in mm)
Safety Relay 2 pole 6 A SCHRACK Source: http://www.schrack.com/.. 5809.pdf
drill 1.3 round: 11 7.54,-3.75; 12 2.54,-3.75; 14 12.54,-3.75; 21 7.54,3.75; 22 2.54,3.75; 24 12.54,3.75; A1 -12.46,-3.75; A2 -12.46,3.75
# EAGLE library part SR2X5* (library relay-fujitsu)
Safety Relay 2 pole 6 A SCHRACK Source: http://www.schrack.com/.. 5809.pdf

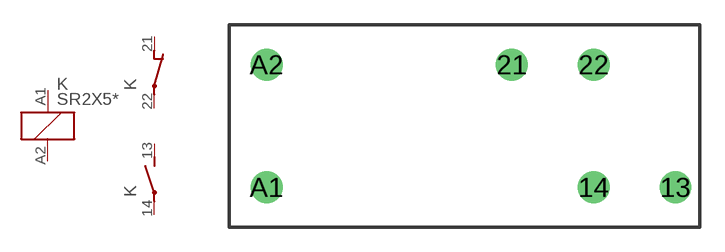
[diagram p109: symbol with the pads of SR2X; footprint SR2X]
Designator prefix K; gates 1=K 2=O 3=S

## SR2X5005, SR2X5006, SR2X5009, SR2X5012, SR2X5018, SR2X5021, SR2X5024, SR2X5036, SR2X5040, SR2X5048, SR2X5060, SR2X5080, SR2X5110  [SR2X]
13  3:S  pas
14  3:P  pas
21  2:O  pas
22  2:P  pas
A1  1:1  pas
A2  1:2  pas

## Footprint SR2X (pad centres in mm)
Safety Relay 2 pole 6 A SCHRACK Source: http://www.schrack.com/.. 5807.pdf
drill 1.3 round: 13 12.54,-3.75; 14 7.54,-3.75; 21 2.54,3.75; 22 7.54,3.75; A1 -12.46,-3.75; A2 -12.46,3.75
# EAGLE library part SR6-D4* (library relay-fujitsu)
Safety Relay 4 pole 8 A SCHRACK 2 N/O contact and 2 N/C contact Source: http://www.schrack.com/.. 5814.pdf

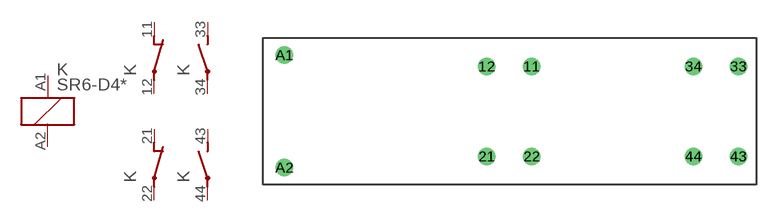
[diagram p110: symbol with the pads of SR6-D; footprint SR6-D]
Designator prefix K; gates 1=K 2=O 3=O 4=S 5=S

## SR6-D4005, SR6-D4006, SR6-D4009, SR6-D4012, SR6-D4018, SR6-D4021, SR6-D4024, SR6-D4036, SR6-D4040, SR6-D4048, SR6-D4060, SR6-D4085, SR6-D4110  [SR6-D]
11  2:O  pas
12  2:P  pas
21  3:O  pas
22  3:P  pas
33  4:S  pas
34  4:P  pas
43  5:S  pas
44  5:P  pas
A1  1:1  pas
A2  1:2  pas

## Footprint SR6-D (pad centres in mm)
Safety Relay 4 pole 8 A SCHRACK 2 N/O contact and 2 N/C contact Source: http://www.schrack.com/.. 5814.pdf
drill 1.3 round: 11 2.5,5; 12 -2.5,5; 21 -2.5,-5; 22 2.5,-5; 33 25.5,5; 34 20.5,5; 43 25.5,-5; 44 20.5,-5; A1 -25,6.25; A2 -25,-6.25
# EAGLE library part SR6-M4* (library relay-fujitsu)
Safety Relay 4 pole 8 A SCHRACK 3 N/O contact and 1 N/C contact Source: http://www.schrack.com/.. 5814.pdf

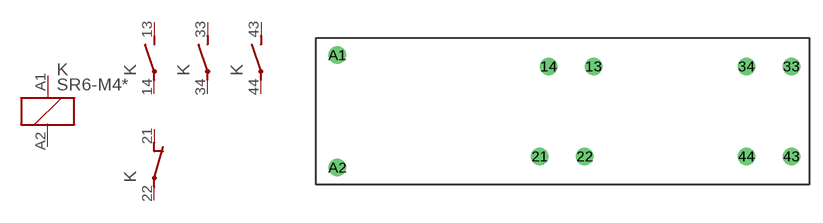
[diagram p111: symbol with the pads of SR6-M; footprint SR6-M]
Designator prefix K; gates 1=K 2=S 3=S 4=S 5=O

## SR6-M4005, SR6-M4006, SR6-M4009, SR6-M4012, SR6-M4018, SR6-M4021, SR6-M4024, SR6-M4036, SR6-M4040, SR6-M4048, SR6-M4060, SR6-M4085, SR6-M4110  [SR6-M]
13  2:S  pas
14  2:P  pas
21  5:O  pas
22  5:P  pas
33  3:S  pas
34  3:P  pas
43  4:S  pas
44  4:P  pas
A1  1:1  pas
A2  1:2  pas

## Footprint SR6-M (pad centres in mm)
Safety Relay 4 pole 8 A SCHRACK Configuration 3 N/O contact and 1 N/C contact Source: http://www.schrack.com/.. 5814.pdf
drill 1.3 round: 13 3.5,5; 14 -1.5,5; 21 -2.5,-5; 22 2.5,-5; 33 25.5,5; 34 20.5,5; 43 25.5,-5; 44 20.5,-5; A1 -25,6.25; A2 -25,-6.25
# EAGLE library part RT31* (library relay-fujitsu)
Power PCB Relayl SCHRACK 1 pole 12 / 16 A, DC- or AC-coi Source: http://www.schrack.com/.. 5819.pdf

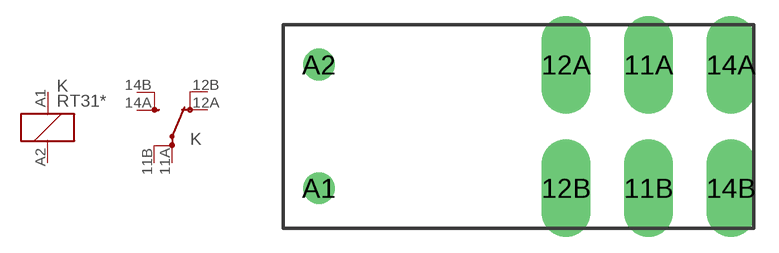
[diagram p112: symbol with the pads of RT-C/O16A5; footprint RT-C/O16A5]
Designator prefix K; gates 1=K 2=U-X2

## RT314005, RT314006, RT314012, RT314024, RT314048, RT314060, RT314110, RT314524, RT314615, RT314730  [RT-C/O16A5]
11A  2:PA  pas
11B  2:PB  pas
12A  2:OA  pas
12B  2:OB  pas
14A  2:SA  pas
14B  2:SB  pas
A1  1:1  pas
A2  1:2  pas

## Footprint RT-C/O16A5 (pad centres in mm)
Power PCB Relay 1 pole 12 / 16 A, DC- or AC-coil SCHRACK 16 A, pinning 5mm Source: http://www.schrack.com/.. 5819.pdf
drill 1.3 pad 3 long: 11A 7.56,3.78; 11B 7.56,-3.78; 12A 2.52,3.78; 12B 2.52,-3.78; 14A 12.6,3.78; 14B 12.6,-3.78
drill 1.3 round: A1 -12.6,-3.78; A2 -12.6,3.78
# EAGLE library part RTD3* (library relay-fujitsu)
Power PCB Relay SCHRACK 1 pole 12 / 16 A, DC- or AC-coil Source: http://www.schrack.com/.. 5819.pdf

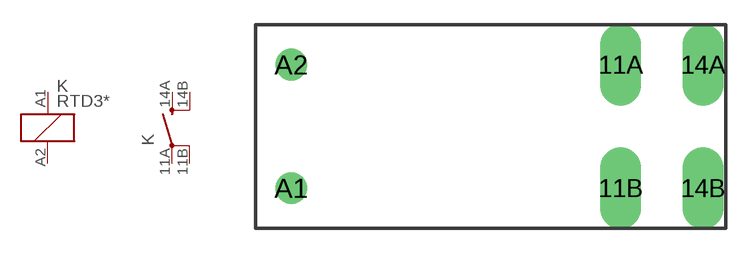
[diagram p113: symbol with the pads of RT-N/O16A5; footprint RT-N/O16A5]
Designator prefix K; gates 1=K 2=S-X2

## RTD34005, RTD34006, RTD34012, RTD34024, RTD34048, RTD34060, RTD34110, RTD34524, RTD34615, RTD34730  [RT-N/O16A5]
11A  2:PA  pas
11B  2:PB  pas
14A  2:SA  pas
14B  2:SB  pas
A1  1:1  pas
A2  1:2  pas

## Footprint RT-N/O16A5 (pad centres in mm)
Power PCB Relay 1 pole 12 / 16 A, DC- or AC-coil SCHRACK 16 A, pinning 5mm Source: http://www.schrack.com/.. 5819.pdf
drill 1.3 pad 2.5 long: 11A 7.56,3.78; 11B 7.56,-3.78; 14A 12.6,3.78; 14B 12.6,-3.78
drill 1.3 round: A1 -12.6,-3.78; A2 -12.6,3.78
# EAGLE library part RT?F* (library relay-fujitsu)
Power PCB Relay SCHRACK bistable 1 pole 16 A, polarized bistable version Source: http://www.schrack.com/.. 5821.pdf

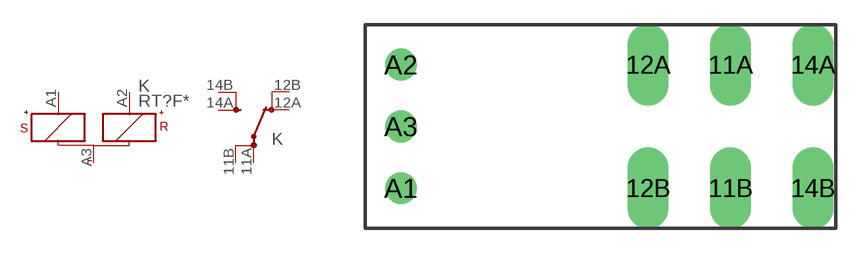
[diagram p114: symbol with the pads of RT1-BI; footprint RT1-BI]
Designator prefix K; gates 1=+KS+KR- 2=U-X2

## RT314F05, RT314F06, RT314F12, RT314F24  [RT1-BI]
11A  2:PA  pas
11B  2:PB  pas
12A  2:OA  pas
12B  2:OB  pas
14A  2:SA  pas
14B  2:SB  pas
A1  1:S+  pas
A2  1:R+  pas
A3  1:-  pas

## RTD14F05, RTD14F06, RTD14F12, RTD14F24  [RT1-BI]
Pads as for RT1-BI

## Footprint RT1-BI (pad centres in mm)
Power PCB Relay , polarized bistable version SCHRACK 1 pole 16 A, pinning 5mm Source: http://www.schrack.com/.. 5821.pdf
drill 1.3 pad 2.5 long: 11A 7.56,3.78; 11B 7.56,-3.78; 12A 2.52,3.78; 12B 2.52,-3.78; 14A 12.6,3.78; 14B 12.6,-3.78
drill 1.3 round: A1 -12.6,-3.78; A2 -12.6,3.78; A3 -12.6,0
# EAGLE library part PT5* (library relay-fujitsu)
Miniature Relay SCHRACK 2 pole 12 A, 3 pole 10 A or 4 pole 6 A DC- or AC-coil Source: http://www.schrack.com/.. 5823.pdf Socked 78604 Source: http://www.schrack.com/.. 5836.pdf

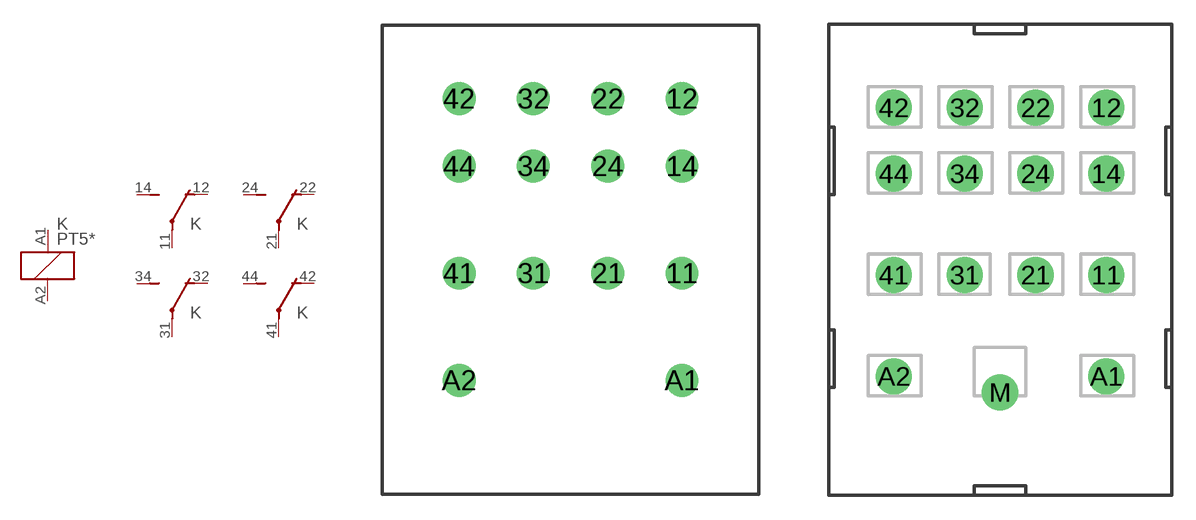
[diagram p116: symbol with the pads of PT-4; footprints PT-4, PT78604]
Designator prefix K; gates 1=K 2=U 3=U 4=U 5=U

## PT571506, PT571512, PT571524, PT571548, PT571560, PT571615, PT571730, PT571R06, PT571R12, PT571R24, PT571R48, PT571R60, PT571S15, PT571T30, PT581506, PT581512, PT581524, PT581548, PT581560, PT581615, PT581730, PT581R06, PT581R12, PT581R24, PT581R48, PT581R60, PT581S15, PT581T30  [PT-4]
11  2:P  pas
12  2:O  pas
14  2:S  pas
21  3:P  pas
22  3:O  pas
24  3:S  pas
31  4:P  pas
32  4:O  pas
34  4:S  pas
41  5:P  pas
42  5:O  pas
44  5:S  pas
A1  1:1  pas
A2  1:2  pas

## PT5-78604  [PT78604]
Pads as for PT-4

## Footprint PT-4 (pad centres in mm)
Miniature Relay SCHRACK 4 pole 6 A DC- or AC-coil Source: http://www.schrack.com/.. 5823.pdf
drill 1.3 round: 11 6.6,6.35; 12 6.6,16.7; 14 6.6,12.7; 21 2.2,6.35; 22 2.2,16.7; 24 2.2,12.7; 31 -2.2,6.35; 32 -2.2,16.7; 34 -2.2,12.7; 41 -6.6,6.35; 42 -6.6,16.7; 44 -6.6,12.7; A1 6.6,0; A2 -6.6,0

## Footprint PT78604 (pad centres in mm)
Accessories Miniature Relay PT SCHRACK Socket with PCB terminals 4 Pol. Source: http://www.schrack.com/.. 5836.pdf
drill 1.5 round: 11 6.6,6.3; 12 6.6,16.7; 14 6.6,12.6; 21 2.2,6.3; 22 2.2,16.7; 24 2.2,12.6; 31 -2.2,6.3; 32 -2.2,16.7; 34 -2.2,12.6; 41 -6.6,6.3; 42 -6.6,16.7; 44 -6.6,12.6; A1 6.6,0; A2 -6.6,0; M 0,-1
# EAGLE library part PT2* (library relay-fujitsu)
Miniature Relay SCHRACK 2 pole 12 A DC- or AC-coil Source: http://www.schrack.com/.. 5823.pdf Socked 78602 Source: http://www.schrack.com/.. 5836.pdf

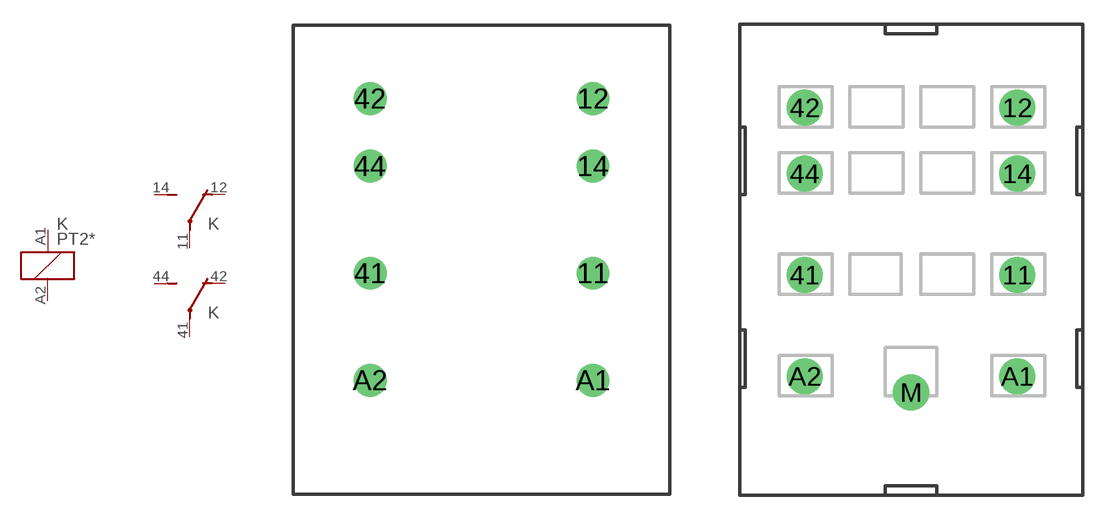
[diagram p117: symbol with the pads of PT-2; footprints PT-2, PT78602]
Designator prefix K; gates 1=K 2=U 3=U

## PT271506, PT271512, PT271524, PT271548, PT271560, PT271615, PT271730, PT271R06, PT271R12, PT271R24, PT271R48, PT271R60, PT271S15, PT271T30, PT281506, PT281512, PT281524, PT281548, PT281560, PT281615, PT281730, PT281R06, PT281R12, PT281R24, PT281R48, PT281R60, PT281S15, PT281T30  [PT-2]
11  2:P  pas
12  2:O  pas
14  2:S  pas
41  3:P  pas
42  3:O  pas
44  3:S  pas
A1  1:1  pas
A2  1:2  pas

## PT2-78602  [PT78602]
Pads as for PT-2

## Footprint PT-2 (pad centres in mm)
Miniature Relay SCHRACK 2 pole 12 A DC- or AC-coil Source: http://www.schrack.com/.. 5823.pdf
drill 1.3 round: 11 6.6,6.35; 12 6.6,16.7; 14 6.6,12.7; 41 -6.6,6.35; 42 -6.6,16.7; 44 -6.6,12.7; A1 6.6,0; A2 -6.6,0

## Footprint PT78602 (pad centres in mm)
Accessories Miniature Relay PT SCHRACK Socket with PCB terminals 2 Pol. Source: http://www.schrack.com/.. 5836.pdf
drill 1.5 round: 11 6.6,6.3; 12 6.6,16.7; 14 6.6,12.6; 41 -6.6,6.3; 42 -6.6,16.7; 44 -6.6,12.6; A1 6.6,0; A2 -6.6,0; M 0,-1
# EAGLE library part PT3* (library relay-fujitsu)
Miniature Relay SCHRACK 3 pole 10 A DC- or AC-coil Source: http://www.schrack.com/.. 5823.pdf Socked 78603 Source: http://www.schrack.com/.. 5836.pdf

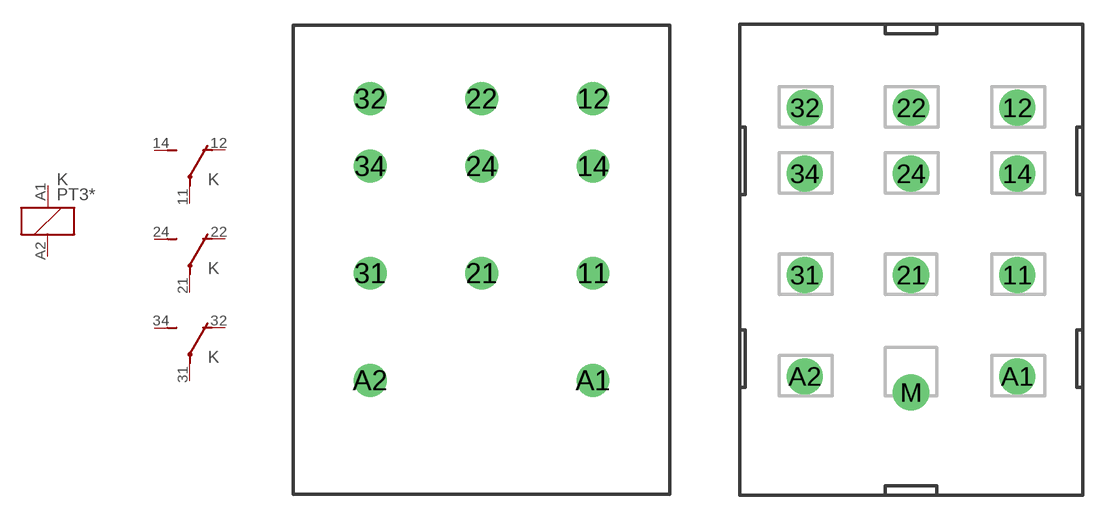
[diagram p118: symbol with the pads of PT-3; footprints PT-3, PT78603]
Designator prefix K; gates 1=K 2=U 3=U 4=U

## PT371506, PT371512, PT371524, PT371548, PT371560, PT371615, PT371730, PT371R06, PT371R12, PT371R24, PT371R48, PT371R60, PT371S15, PT371T30, PT381506, PT381512, PT381524, PT381548, PT381560, PT381615, PT381730, PT381R06, PT381R12, PT381R24, PT381R48, PT381R60, PT381S15, PT381T30  [PT-3]
11  2:P  pas
12  2:O  pas
14  2:S  pas
21  3:P  pas
22  3:O  pas
24  3:S  pas
31  4:P  pas
32  4:O  pas
34  4:S  pas
A1  1:1  pas
A2  1:2  pas

## PT3-78603  [PT78603]
Pads as for PT-3

## Footprint PT-3 (pad centres in mm)
Miniature Relay SCHRACK 3 pole 10 A DC- or AC-coil Source: http://www.schrack.com/.. 5823.pdf
drill 1.3 round: 11 6.6,6.35; 12 6.6,16.7; 14 6.6,12.7; 21 0,6.35; 22 0,16.7; 24 0,12.7; 31 -6.6,6.35; 32 -6.6,16.7; 34 -6.6,12.7; A1 6.6,0; A2 -6.6,0

## Footprint PT78603 (pad centres in mm)
Accessories Miniature Relay PT SCHRACK Socket with PCB terminals 3 Pol. Source: http://www.schrack.com/.. 5836.pdf
drill 1.5 round: 11 6.6,6.3; 12 6.6,16.7; 14 6.6,12.6; 21 0,6.3; 22 0,16.7; 24 0,12.6; 31 -6.6,6.3; 32 -6.6,16.7; 34 -6.6,12.6; A1 6.6,0; A2 -6.6,0; M 0,-1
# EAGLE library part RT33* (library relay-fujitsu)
Power PCB Relay Inrush SCHRACK 1 pole 16 A, for inrush peak currents up to 80 A Source: http://www.schrack.com/.. 5825.pdf

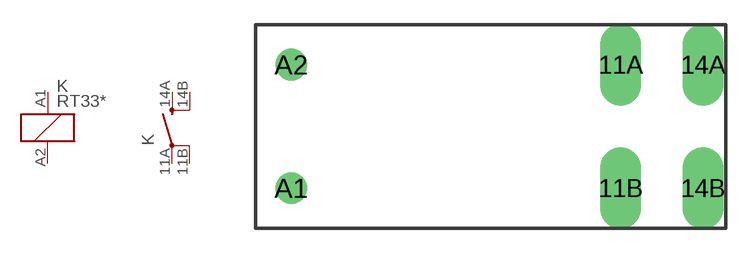
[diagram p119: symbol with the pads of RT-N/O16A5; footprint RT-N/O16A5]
Designator prefix K; gates 1=K 2=S-X2

## RT33K012, RT33K024, RT33K048, RT33K060, RT33L012, RT33L024, RT33L048, RT33L060  [RT-N/O16A5]
11A  2:PA  pas
11B  2:PB  pas
14A  2:SA  pas
14B  2:SB  pas
A1  1:1  pas
A2  1:2  pas

## Footprint RT-N/O16A5 (pad centres in mm)
Power PCB Relay 1 pole 12 / 16 A, DC- or AC-coil SCHRACK 16 A, pinning 5mm Source: http://www.schrack.com/.. 5819.pdf
drill 1.3 pad 2.5 long: 11A 7.56,3.78; 11B 7.56,-3.78; 14A 12.6,3.78; 14B 12.6,-3.78
drill 1.3 round: A1 -12.6,-3.78; A2 -12.6,3.78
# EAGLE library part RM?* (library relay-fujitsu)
Power Relay SCHRACK 3 pole 10 A, DC- or AC-coil Source: http://www.schrack.com/.. 5829.pdf Socket with PCB terminals Source: http://www.schrack.com/.. 5841.pdf

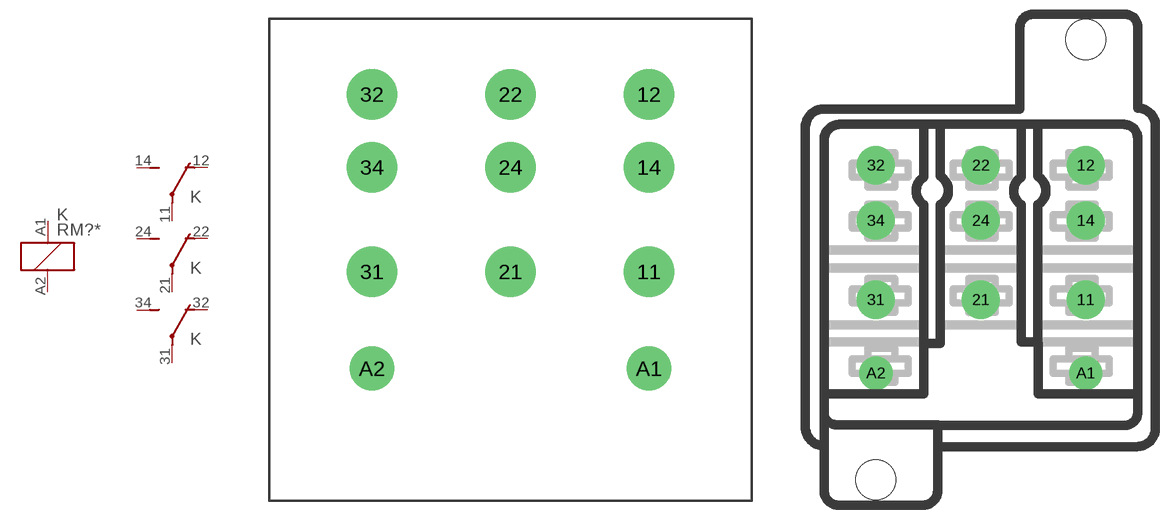
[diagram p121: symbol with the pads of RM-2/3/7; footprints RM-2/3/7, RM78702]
Designator prefix K; gates 1=K 2=U 3=U 4=U

## RM3506, RM3512, RM3524, RM3548, RM3615, RM3730, RM3900, RM3R06, RM3R12, RM3R24, RM3R48, RM3S15, RM3T30, RM3V00  [RM-2/3/7]
11  2:P  pas
12  2:O  pas
14  2:S  pas
21  3:P  pas
22  3:O  pas
24  3:S  pas
31  4:P  pas
32  4:O  pas
34  4:S  pas
A1  1:1  pas
A2  1:2  pas

## RM7506, RM7512, RM7524, RM7548, RM7615, RM7730, RM7900, RM7R06, RM7R12, RM7R24, RM7R48, RM7S15, RM7T30, RM7V00  [RM-2/3/7]
Pads as for RM-2/3/7

## RM78702  [RM78702]
Pads as for RM-2/3/7

## Footprint RM-2/3/7 (pad centres in mm)
Power Relay SCHRACK 2 / 3 pole 10 / 16 A, DC- or AC-coil Source: http://www.schrack.com/.. 5829.pdf
drill 2 pad 4 round: 11 11,-0.95; 12 11,13.15; 14 11,7.35; 21 0,-0.95; 22 0,13.15; 24 0,7.35; 31 -11,-0.95; 32 -11,13.15; 34 -11,7.35
drill 2 pad 3.5 round: A1 11,-8.65; A2 -11,-8.65

## Footprint RM78702 (pad centres in mm)
Power Relay Socket with PCB terminals SCHRACK 3 pole 10 A, DC- or AC-coil Source: http://www.schrack.com/.. 5841.pdf
drill 2 pad 4 round: 11 11,-0.95; 12 11,13.15; 14 11,7.35; 21 0,-0.95; 22 0,13.15; 24 0,7.35; 31 -11,-0.95; 32 -11,13.15; 34 -11,7.35
drill 2 pad 3.5 round: A1 11,-8.65; A2 -11,-8.65
hole 4.2 at -11,-19.85
hole 4.2 at 11,26.35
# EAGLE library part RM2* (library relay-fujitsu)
Power Relay SCHRACK 2 pole 16 A, DC- or AC-coil Source: http://www.schrack.com/.. 5829.pdf

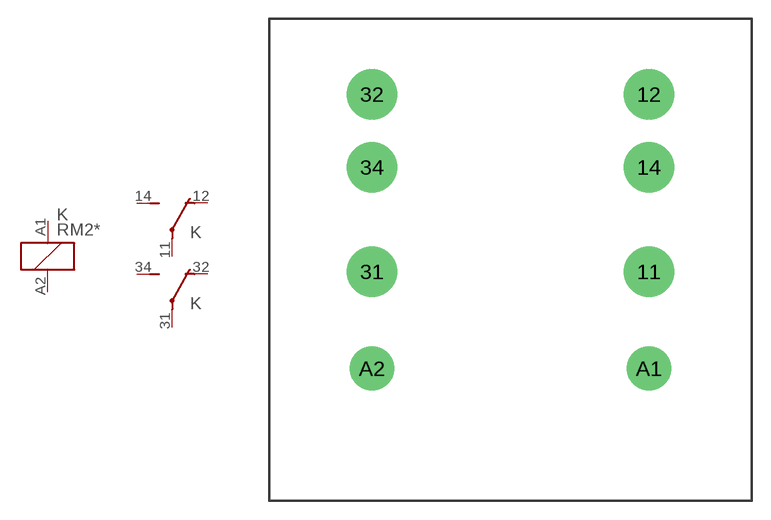
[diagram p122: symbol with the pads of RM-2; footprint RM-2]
Designator prefix K; gates 1=K 2=U 3=U

## RM2506, RM2512, RM2524, RM2548, RM2615, RM2730, RM2900, RM2R06, RM2R12, RM2R24, RM2R48, RM2S15, RM2T30, RM2V00  [RM-2]
11  2:P  pas
12  2:O  pas
14  2:S  pas
31  3:P  pas
32  3:O  pas
34  3:S  pas
A1  1:1  pas
A2  1:2  pas

## Footprint RM-2 (pad centres in mm)
Power Relay SCHRACK 2 pole 16 A, DC- or AC-coil Source: http://www.schrack.com/.. 5829.pdf
drill 2 pad 4 round: 11 11,-0.95; 12 11,13.15; 14 11,7.35; 31 -11,-0.95; 32 -11,13.15; 34 -11,7.35
drill 2 pad 3.5 round: A1 11,-8.65; A2 -11,-8.65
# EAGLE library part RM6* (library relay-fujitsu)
Power Relay SCHRACK 3 pole 10 A, DC- or AC-coil Source: http://www.schrack.com/.. 5832.pdf

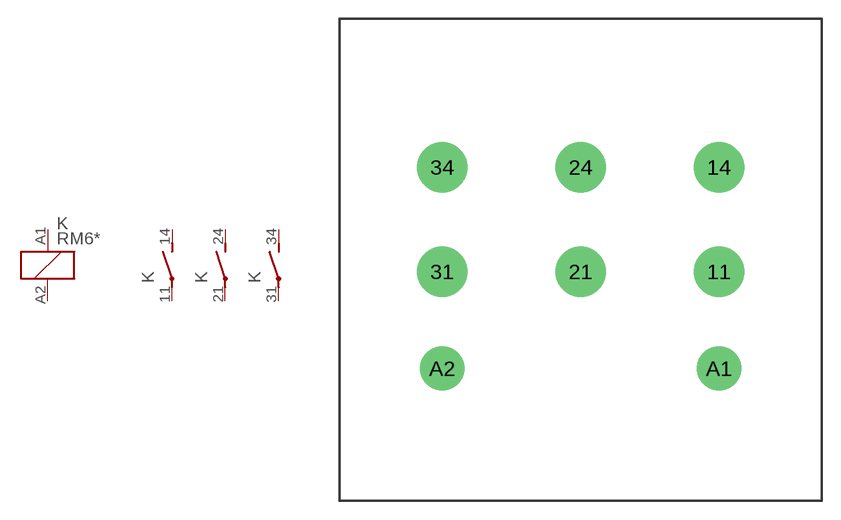
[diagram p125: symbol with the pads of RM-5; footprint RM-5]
Designator prefix K; gates 1=K 2=S 3=S 4=S

## RM607506, RM607512, RM607524, RM607548, RM607560, RM607615, RM607730, RM607900, RM607R06, RM607R12, RM607R24, RM607R48, RM607R60, RM607S15, RM607T30, RM607V00  [RM-5]
11  2:P  pas
14  2:S  pas
21  3:P  pas
24  3:S  pas
31  4:P  pas
34  4:S  pas
A1  1:1  pas
A2  1:2  pas

## Footprint RM-5 (pad centres in mm)
Power Relay SCHRACK 3 pole 10 A, DC- or AC-coil Source: http://www.schrack.com/.. 5832.pdf
drill 2 pad 4 round: 11 11,-0.95; 14 11,7.35; 21 0,-0.95; 24 0,7.35; 31 -11,-0.95; 34 -11,7.35
drill 2 pad 3.5 round: A1 11,-8.65; A2 -11,-8.65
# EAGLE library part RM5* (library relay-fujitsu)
Power Relay SCHRACK 2 pole 16 A, DC- or AC-coil Source: http://www.schrack.com/.. 5832.pdf

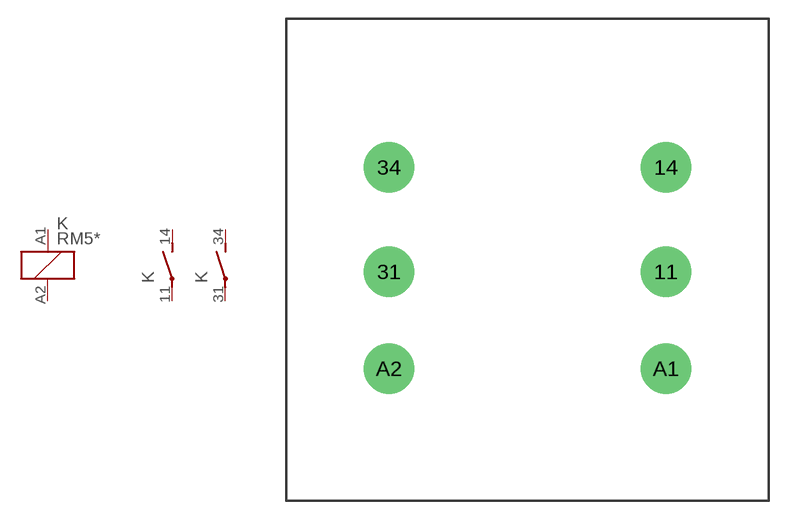
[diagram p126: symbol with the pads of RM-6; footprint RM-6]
Designator prefix K; gates 1=K 2=S 3=S

## RM507506, RM507512, RM507524, RM507548, RM507560, RM507615, RM507730, RM507900, RM507R06, RM507R12, RM507R24, RM507R48, RM507R60, RM507S15, RM507T30, RM507V00  [RM-6]
11  2:P  pas
14  2:S  pas
31  3:P  pas
34  3:S  pas
A1  1:1  pas
A2  1:2  pas

## Footprint RM-6 (pad centres in mm)
Power Relay SCHRACK 2 pole 16 A, DC- or AC-coil Source: http://www.schrack.com/.. 5832.pdf
drill 2 pad 4 round: 11 11,-0.95; 14 11,7.35; 31 -11,-0.95; 34 -11,7.35; A1 11,-8.65; A2 -11,-8.65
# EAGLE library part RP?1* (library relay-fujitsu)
Power PCB Relay RP II/1 SCHRACK 1 pole 16 A Source: http://www.schrack.com/.. 5834.pdf

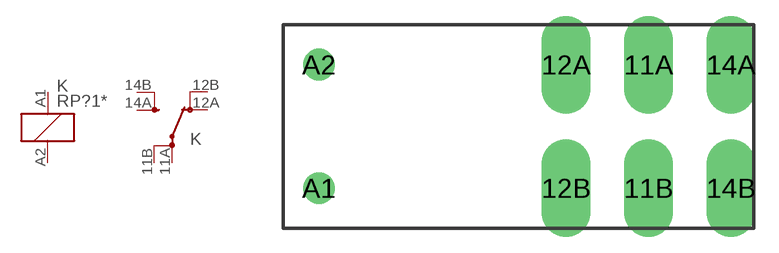
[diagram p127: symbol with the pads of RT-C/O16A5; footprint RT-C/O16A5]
Designator prefix K; gates 1=K 2=U-X2

## RP310005, RP310006, RP310012, RP310024, RP310048, RP310060, RP310110  [RT-C/O16A5]
11A  2:PA  pas
11B  2:PB  pas
12A  2:OA  pas
12B  2:OB  pas
14A  2:SA  pas
14B  2:SB  pas
A1  1:1  pas
A2  1:2  pas

## RP710005, RP710006, RP710012, RP710024, RP710048, RP710060, RP710110  [RT-C/O16A5]
Pads as for RT-C/O16A5

## Footprint RT-C/O16A5 (pad centres in mm)
Power PCB Relay 1 pole 12 / 16 A, DC- or AC-coil SCHRACK 16 A, pinning 5mm Source: http://www.schrack.com/.. 5819.pdf
drill 1.3 pad 3 long: 11A 7.56,3.78; 11B 7.56,-3.78; 12A 2.52,3.78; 12B 2.52,-3.78; 14A 12.6,3.78; 14B 12.6,-3.78
drill 1.3 round: A1 -12.6,-3.78; A2 -12.6,3.78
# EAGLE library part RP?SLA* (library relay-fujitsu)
Special Load PCB Relay SCHRACK 1 pole 16 A, for high inrush currents, monostable Source: http://www.schrack.com/.. 5837.pdf

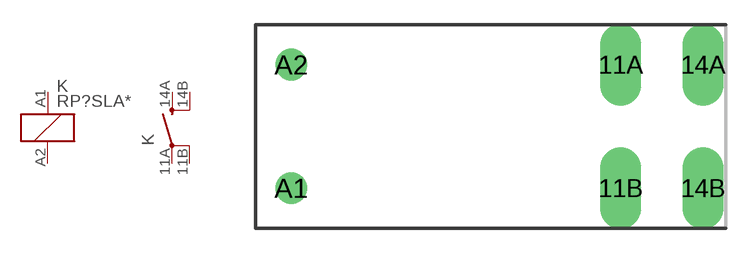
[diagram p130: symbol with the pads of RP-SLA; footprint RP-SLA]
Designator prefix K; gates 1=K 2=S-X2

## RP3SLA05, RP3SLA12, RP3SLA24  [RP-SLA]
11A  2:PA  pas
11B  2:PB  pas
14A  2:SA  pas
14B  2:SB  pas
A1  1:1  pas
A2  1:2  pas

## RP7SLA05, RP7SLA12, RP7SLA24  [RP-SLA]
Pads as for RP-SLA

## Footprint RP-SLA (pad centres in mm)
Special Load PCB Relay SCHRACK 1 pole 16 A, for high inrush currents, monostable Source: http://www.schrack.com/.. 5837.pdf
drill 1.3 pad 2.5 long: 11A 7.56,3.78; 11B 7.56,-3.78; 14A 12.6,3.78; 14B 12.6,-3.78
drill 1.3 round: A1 -12.6,-3.78; A2 -12.6,3.78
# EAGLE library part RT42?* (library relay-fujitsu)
Power PCB Relay SCHRACK 2 pole 8 A, DC and AC-coil Source: http://www.schrack.com/.. 5842.pdf

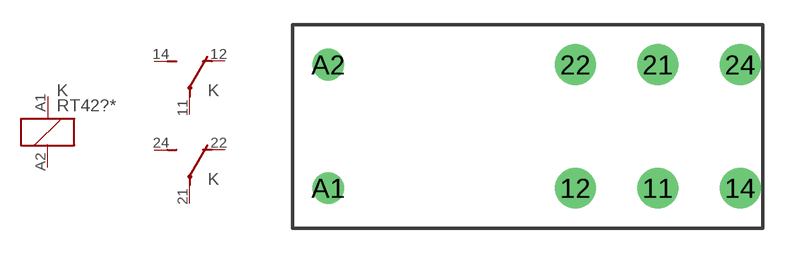
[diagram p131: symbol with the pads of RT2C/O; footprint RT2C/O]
Designator prefix K; gates 1=K 2=U 3=U

## RT424005, RT424006, RT424012, RT424024, RT424048, RT424060, RT424110, RT424524, RT424615, RT424730  [RT2C/O]
11  2:P  pas
12  2:O  pas
14  2:S  pas
21  3:P  pas
22  3:O  pas
24  3:S  pas
A1  1:1  pas
A2  1:2  pas

## RT425005, RT425006, RT425012, RT425024, RT425048, RT425060, RT425110, RT425524, RT425615, RT425730  [RT2C/O]
11  3:P  pas
12  3:O  pas
14  3:S  pas
21  2:P  pas
22  2:O  pas
24  2:S  pas
A1  1:1  pas
A2  1:2  pas

## Footprint RT2C/O (pad centres in mm)
Power PCB Relay DC and AC-coil SCHRACK 2 pole 8 A Source: http://www.schrack.com/.. 5842.pdf
drill 1.3 pad 2.5 round: 11 7.56,-3.68; 12 2.52,-3.68; 14 12.6,-3.68; 21 7.56,3.88; 22 2.52,3.88; 24 12.6,3.88
drill 1.3 round: A1 -12.6,-3.68; A2 -12.6,3.88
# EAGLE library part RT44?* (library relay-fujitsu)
Power PCB Relay SCHRACK 2 pole 8 A, DC and AC-coil Source: http://www.schrack.com/.. 5842.pdf

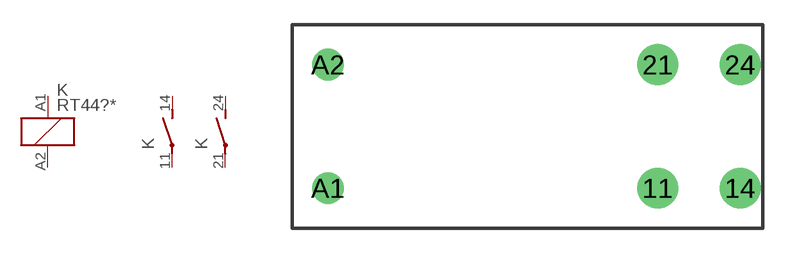
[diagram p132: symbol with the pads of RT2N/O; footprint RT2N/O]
Designator prefix K; gates 1=K 2=S 3=S

## RT444005, RT444006, RT444012, RT444024, RT444048, RT444060, RT444110, RT444524, RT444615, RT444730  [RT2N/O]
11  2:P  pas
14  2:S  pas
21  3:P  pas
24  3:S  pas
A1  1:1  pas
A2  1:2  pas

## RT445005, RT445006, RT445012, RT445024, RT445048, RT445060, RT445110, RT445524, RT445615, RT445730  [RT2N/O]
Pads as for RT2N/O

## Footprint RT2N/O (pad centres in mm)
Power PCB Relay DC and AC-coil SCHRACK 2 pole 8 A Source: http://www.schrack.com/.. 5842.pdf
drill 1.3 pad 2.5 round: 11 7.56,-3.78; 14 12.6,-3.78; 21 7.56,3.78; 24 12.6,3.78
drill 1.3 round: A1 -12.6,-3.78; A2 -12.6,3.78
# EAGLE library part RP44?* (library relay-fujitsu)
Power PCB Relay RP II/2 Schrack 2 pole 8 A Source: http://www.schrack.com/.. 5844.pdf

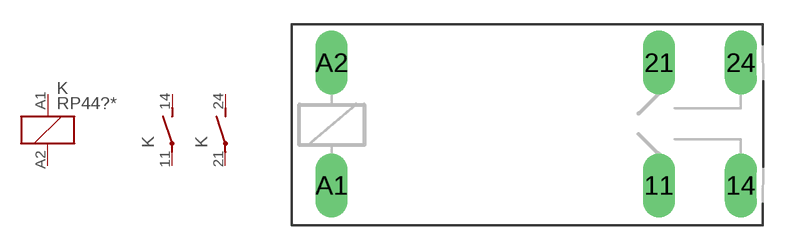
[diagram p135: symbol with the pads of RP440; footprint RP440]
Designator prefix K; gates 1=K 2=S 3=S

## RP440005, RP440006, RP440012, RP440024, RP440048, RP440060, RP440110, RP441005, RP441006, RP441012, RP441024, RP441048, RP441060, RP441110  [RP440]
11  2:P  pas
14  2:S  pas
21  3:P  pas
24  3:S  pas
A1  1:1  pas
A2  1:2  pas

## Footprint RP440 (pad centres in mm)
Power PCB Relay RP II/2 SCHRACK 2 pole 8 A Source: http://www.schrack.com/.. 5844.pdf
drill 1.321 long: 11 16.51,-3.81; 14 21.59,-3.81; 21 16.51,3.81; 24 21.59,3.81; A1 -3.81,-3.81; A2 -3.81,3.81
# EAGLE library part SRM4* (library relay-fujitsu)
Safety Relay SCHRACK 4 pole 8 A Source: http://www.schrack.com/.. 6685.pdf

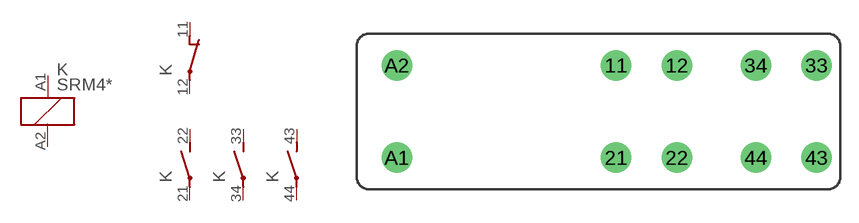
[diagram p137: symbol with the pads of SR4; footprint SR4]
Designator prefix K; gates 1=K 2=O 3=S 4=S 5=S

## SRM4005, SRM4006, SRM4009, SRM4012, SRM4015, SRM4018, SRM4021, SRM4024, SRM4036, SRM4040, SRM4048, SRM4060, SRM4085, SRM4110  [SR4]
11  2:O  pas
12  2:P  pas
21  3:P  pas
22  3:S  pas
33  4:S  pas
34  4:P  pas
43  5:S  pas
44  5:P  pas
A1  1:1  pas
A2  1:2  pas

## Footprint SR4 (pad centres in mm)
Safety Relay SCHRACK 4 pole 8 A Source: http://www.schrack.com/.. 6685.pdf
drill 1.3 pad 2.5 round: 11 0,3.8; 12 5,3.8; 21 0,-3.8; 22 5,-3.8; 33 16.5,3.8; 34 11.5,3.8; 43 16.5,-3.8; 44 11.5,-3.8; A1 -18.05,-3.8; A2 -18.05,3.8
